VERSION 5.8 ;
BUSBITCHARS "[]" ;
DIVIDERCHAR "/" ;
UNITS
    DATABASE MICRONS 1000 ;
END UNITS

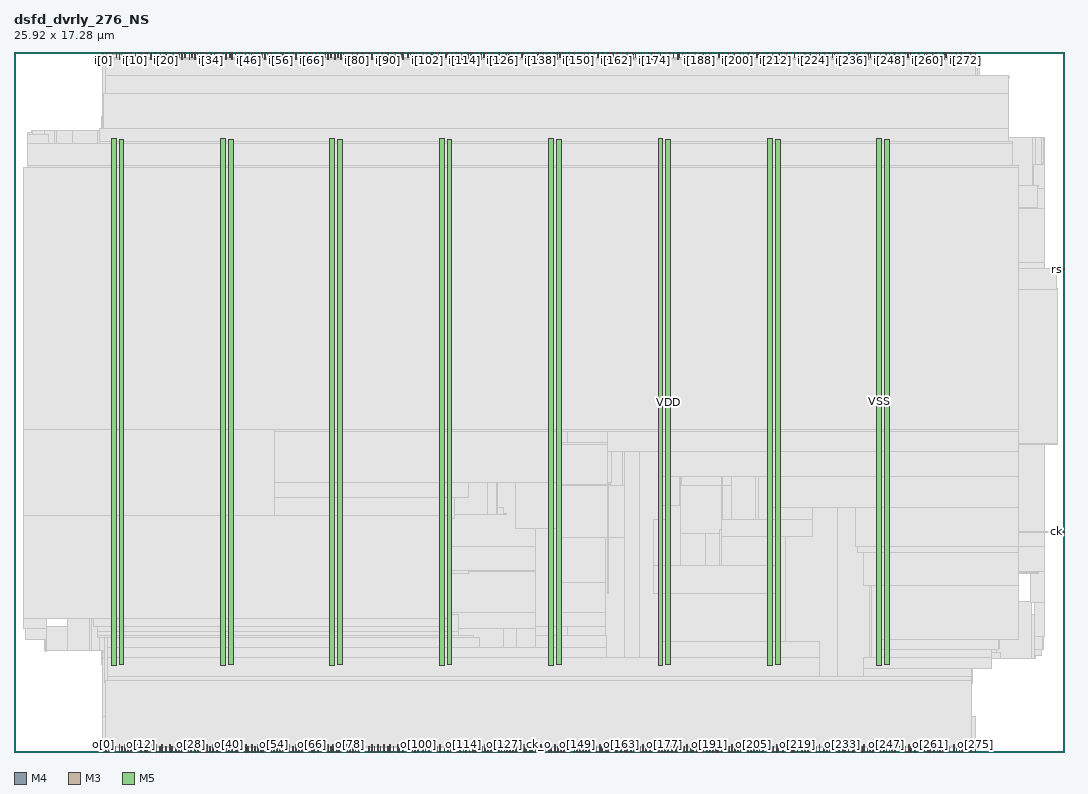
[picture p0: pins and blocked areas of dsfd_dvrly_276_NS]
MACRO dsfd_dvrly_276_NS
  FOREIGN dsfd_dvrly_276_NS 0 0 ;
  CLASS BLOCK ;
  SIZE 25.92 BY 17.28 ;
  PIN ck
    DIRECTION INPUT ;
    USE SIGNAL ;
    PORT
      LAYER M4 ;
        RECT  25.728 5.424 25.92 5.448 ;
    END
  END ck
  PIN ck_o
    DIRECTION OUTPUT ;
    USE SIGNAL ;
    PORT
      LAYER M3 ;
        RECT  12.96 0 12.978 0.144 ;
    END
  END ck_o
  PIN i[0]
    DIRECTION INPUT ;
    USE SIGNAL ;
    PORT
      LAYER M3 ;
        RECT  2.196 17.136 2.214 17.28 ;
    END
  END i[0]
  PIN i[100]
    DIRECTION INPUT ;
    USE SIGNAL ;
    PORT
      LAYER M3 ;
        RECT  10.008 17.136 10.026 17.28 ;
    END
  END i[100]
  PIN i[101]
    DIRECTION INPUT ;
    USE SIGNAL ;
    PORT
      LAYER M5 ;
        RECT  10.08 17.088 10.104 17.28 ;
    END
  END i[101]
  PIN i[102]
    DIRECTION INPUT ;
    USE SIGNAL ;
    PORT
      LAYER M3 ;
        RECT  10.188 17.136 10.206 17.28 ;
    END
  END i[102]
  PIN i[103]
    DIRECTION INPUT ;
    USE SIGNAL ;
    PORT
      LAYER M5 ;
        RECT  10.272 17.088 10.296 17.28 ;
    END
  END i[103]
  PIN i[104]
    DIRECTION INPUT ;
    USE SIGNAL ;
    PORT
      LAYER M3 ;
        RECT  10.332 17.136 10.35 17.28 ;
    END
  END i[104]
  PIN i[105]
    DIRECTION INPUT ;
    USE SIGNAL ;
    PORT
      LAYER M5 ;
        RECT  10.416 17.088 10.44 17.28 ;
    END
  END i[105]
  PIN i[106]
    DIRECTION INPUT ;
    USE SIGNAL ;
    PORT
      LAYER M3 ;
        RECT  10.476 17.136 10.494 17.28 ;
    END
  END i[106]
  PIN i[107]
    DIRECTION INPUT ;
    USE SIGNAL ;
    PORT
      LAYER M5 ;
        RECT  10.56 17.088 10.584 17.28 ;
    END
  END i[107]
  PIN i[108]
    DIRECTION INPUT ;
    USE SIGNAL ;
    PORT
      LAYER M3 ;
        RECT  10.656 17.136 10.674 17.28 ;
    END
  END i[108]
  PIN i[109]
    DIRECTION INPUT ;
    USE SIGNAL ;
    PORT
      LAYER M5 ;
        RECT  10.704 17.088 10.728 17.28 ;
    END
  END i[109]
  PIN i[10]
    DIRECTION INPUT ;
    USE SIGNAL ;
    PORT
      LAYER M3 ;
        RECT  2.988 17.136 3.006 17.28 ;
    END
  END i[10]
  PIN i[110]
    DIRECTION INPUT ;
    USE SIGNAL ;
    PORT
      LAYER M3 ;
        RECT  10.8 17.136 10.818 17.28 ;
    END
  END i[110]
  PIN i[111]
    DIRECTION INPUT ;
    USE SIGNAL ;
    PORT
      LAYER M5 ;
        RECT  10.896 17.088 10.92 17.28 ;
    END
  END i[111]
  PIN i[112]
    DIRECTION INPUT ;
    USE SIGNAL ;
    PORT
      LAYER M3 ;
        RECT  10.944 17.136 10.962 17.28 ;
    END
  END i[112]
  PIN i[113]
    DIRECTION INPUT ;
    USE SIGNAL ;
    PORT
      LAYER M5 ;
        RECT  11.04 17.088 11.064 17.28 ;
    END
  END i[113]
  PIN i[114]
    DIRECTION INPUT ;
    USE SIGNAL ;
    PORT
      LAYER M3 ;
        RECT  11.124 17.136 11.142 17.28 ;
    END
  END i[114]
  PIN i[115]
    DIRECTION INPUT ;
    USE SIGNAL ;
    PORT
      LAYER M5 ;
        RECT  11.184 17.088 11.208 17.28 ;
    END
  END i[115]
  PIN i[116]
    DIRECTION INPUT ;
    USE SIGNAL ;
    PORT
      LAYER M3 ;
        RECT  11.268 17.136 11.286 17.28 ;
    END
  END i[116]
  PIN i[117]
    DIRECTION INPUT ;
    USE SIGNAL ;
    PORT
      LAYER M5 ;
        RECT  11.328 17.088 11.352 17.28 ;
    END
  END i[117]
  PIN i[118]
    DIRECTION INPUT ;
    USE SIGNAL ;
    PORT
      LAYER M3 ;
        RECT  11.412 17.136 11.43 17.28 ;
    END
  END i[118]
  PIN i[119]
    DIRECTION INPUT ;
    USE SIGNAL ;
    PORT
      LAYER M5 ;
        RECT  11.52 17.088 11.544 17.28 ;
    END
  END i[119]
  PIN i[11]
    DIRECTION INPUT ;
    USE SIGNAL ;
    PORT
      LAYER M5 ;
        RECT  3.072 17.088 3.096 17.28 ;
    END
  END i[11]
  PIN i[120]
    DIRECTION INPUT ;
    USE SIGNAL ;
    PORT
      LAYER M3 ;
        RECT  11.592 17.136 11.61 17.28 ;
    END
  END i[120]
  PIN i[121]
    DIRECTION INPUT ;
    USE SIGNAL ;
    PORT
      LAYER M5 ;
        RECT  11.664 17.088 11.688 17.28 ;
    END
  END i[121]
  PIN i[122]
    DIRECTION INPUT ;
    USE SIGNAL ;
    PORT
      LAYER M3 ;
        RECT  11.736 17.136 11.754 17.28 ;
    END
  END i[122]
  PIN i[123]
    DIRECTION INPUT ;
    USE SIGNAL ;
    PORT
      LAYER M5 ;
        RECT  11.808 17.088 11.832 17.28 ;
    END
  END i[123]
  PIN i[124]
    DIRECTION INPUT ;
    USE SIGNAL ;
    PORT
      LAYER M3 ;
        RECT  11.88 17.136 11.898 17.28 ;
    END
  END i[124]
  PIN i[125]
    DIRECTION INPUT ;
    USE SIGNAL ;
    PORT
      LAYER M5 ;
        RECT  11.952 17.088 11.976 17.28 ;
    END
  END i[125]
  PIN i[126]
    DIRECTION INPUT ;
    USE SIGNAL ;
    PORT
      LAYER M3 ;
        RECT  12.06 17.136 12.078 17.28 ;
    END
  END i[126]
  PIN i[127]
    DIRECTION INPUT ;
    USE SIGNAL ;
    PORT
      LAYER M5 ;
        RECT  12.144 17.088 12.168 17.28 ;
    END
  END i[127]
  PIN i[128]
    DIRECTION INPUT ;
    USE SIGNAL ;
    PORT
      LAYER M3 ;
        RECT  12.204 17.136 12.222 17.28 ;
    END
  END i[128]
  PIN i[129]
    DIRECTION INPUT ;
    USE SIGNAL ;
    PORT
      LAYER M5 ;
        RECT  12.288 17.088 12.312 17.28 ;
    END
  END i[129]
  PIN i[12]
    DIRECTION INPUT ;
    USE SIGNAL ;
    PORT
      LAYER M3 ;
        RECT  3.132 17.136 3.15 17.28 ;
    END
  END i[12]
  PIN i[130]
    DIRECTION INPUT ;
    USE SIGNAL ;
    PORT
      LAYER M3 ;
        RECT  12.348 17.136 12.366 17.28 ;
    END
  END i[130]
  PIN i[131]
    DIRECTION INPUT ;
    USE SIGNAL ;
    PORT
      LAYER M5 ;
        RECT  12.432 17.088 12.456 17.28 ;
    END
  END i[131]
  PIN i[132]
    DIRECTION INPUT ;
    USE SIGNAL ;
    PORT
      LAYER M3 ;
        RECT  12.528 17.136 12.546 17.28 ;
    END
  END i[132]
  PIN i[133]
    DIRECTION INPUT ;
    USE SIGNAL ;
    PORT
      LAYER M5 ;
        RECT  12.576 17.088 12.6 17.28 ;
    END
  END i[133]
  PIN i[134]
    DIRECTION INPUT ;
    USE SIGNAL ;
    PORT
      LAYER M3 ;
        RECT  12.672 17.136 12.69 17.28 ;
    END
  END i[134]
  PIN i[135]
    DIRECTION INPUT ;
    USE SIGNAL ;
    PORT
      LAYER M5 ;
        RECT  12.768 17.088 12.792 17.28 ;
    END
  END i[135]
  PIN i[136]
    DIRECTION INPUT ;
    USE SIGNAL ;
    PORT
      LAYER M3 ;
        RECT  12.816 17.136 12.834 17.28 ;
    END
  END i[136]
  PIN i[137]
    DIRECTION INPUT ;
    USE SIGNAL ;
    PORT
      LAYER M5 ;
        RECT  12.912 17.088 12.936 17.28 ;
    END
  END i[137]
  PIN i[138]
    DIRECTION INPUT ;
    USE SIGNAL ;
    PORT
      LAYER M3 ;
        RECT  12.996 17.136 13.014 17.28 ;
    END
  END i[138]
  PIN i[139]
    DIRECTION INPUT ;
    USE SIGNAL ;
    PORT
      LAYER M5 ;
        RECT  13.056 17.088 13.08 17.28 ;
    END
  END i[139]
  PIN i[13]
    DIRECTION INPUT ;
    USE SIGNAL ;
    PORT
      LAYER M5 ;
        RECT  3.216 17.088 3.24 17.28 ;
    END
  END i[13]
  PIN i[140]
    DIRECTION INPUT ;
    USE SIGNAL ;
    PORT
      LAYER M3 ;
        RECT  13.14 17.136 13.158 17.28 ;
    END
  END i[140]
  PIN i[141]
    DIRECTION INPUT ;
    USE SIGNAL ;
    PORT
      LAYER M5 ;
        RECT  13.2 17.088 13.224 17.28 ;
    END
  END i[141]
  PIN i[142]
    DIRECTION INPUT ;
    USE SIGNAL ;
    PORT
      LAYER M3 ;
        RECT  13.32 17.136 13.338 17.28 ;
    END
  END i[142]
  PIN i[143]
    DIRECTION INPUT ;
    USE SIGNAL ;
    PORT
      LAYER M5 ;
        RECT  13.392 17.088 13.416 17.28 ;
    END
  END i[143]
  PIN i[144]
    DIRECTION INPUT ;
    USE SIGNAL ;
    PORT
      LAYER M3 ;
        RECT  13.464 17.136 13.482 17.28 ;
    END
  END i[144]
  PIN i[145]
    DIRECTION INPUT ;
    USE SIGNAL ;
    PORT
      LAYER M5 ;
        RECT  13.536 17.088 13.56 17.28 ;
    END
  END i[145]
  PIN i[146]
    DIRECTION INPUT ;
    USE SIGNAL ;
    PORT
      LAYER M3 ;
        RECT  13.608 17.136 13.626 17.28 ;
    END
  END i[146]
  PIN i[147]
    DIRECTION INPUT ;
    USE SIGNAL ;
    PORT
      LAYER M5 ;
        RECT  13.68 17.088 13.704 17.28 ;
    END
  END i[147]
  PIN i[148]
    DIRECTION INPUT ;
    USE SIGNAL ;
    PORT
      LAYER M3 ;
        RECT  13.788 17.136 13.806 17.28 ;
    END
  END i[148]
  PIN i[149]
    DIRECTION INPUT ;
    USE SIGNAL ;
    PORT
      LAYER M5 ;
        RECT  13.824 17.088 13.848 17.28 ;
    END
  END i[149]
  PIN i[14]
    DIRECTION INPUT ;
    USE SIGNAL ;
    PORT
      LAYER M3 ;
        RECT  3.276 17.136 3.294 17.28 ;
    END
  END i[14]
  PIN i[150]
    DIRECTION INPUT ;
    USE SIGNAL ;
    PORT
      LAYER M3 ;
        RECT  13.932 17.136 13.95 17.28 ;
    END
  END i[150]
  PIN i[151]
    DIRECTION INPUT ;
    USE SIGNAL ;
    PORT
      LAYER M5 ;
        RECT  14.016 17.088 14.04 17.28 ;
    END
  END i[151]
  PIN i[152]
    DIRECTION INPUT ;
    USE SIGNAL ;
    PORT
      LAYER M3 ;
        RECT  14.076 17.136 14.094 17.28 ;
    END
  END i[152]
  PIN i[153]
    DIRECTION INPUT ;
    USE SIGNAL ;
    PORT
      LAYER M5 ;
        RECT  14.16 17.088 14.184 17.28 ;
    END
  END i[153]
  PIN i[154]
    DIRECTION INPUT ;
    USE SIGNAL ;
    PORT
      LAYER M3 ;
        RECT  14.256 17.136 14.274 17.28 ;
    END
  END i[154]
  PIN i[155]
    DIRECTION INPUT ;
    USE SIGNAL ;
    PORT
      LAYER M5 ;
        RECT  14.304 17.088 14.328 17.28 ;
    END
  END i[155]
  PIN i[156]
    DIRECTION INPUT ;
    USE SIGNAL ;
    PORT
      LAYER M3 ;
        RECT  14.4 17.136 14.418 17.28 ;
    END
  END i[156]
  PIN i[157]
    DIRECTION INPUT ;
    USE SIGNAL ;
    PORT
      LAYER M5 ;
        RECT  14.496 17.088 14.52 17.28 ;
    END
  END i[157]
  PIN i[158]
    DIRECTION INPUT ;
    USE SIGNAL ;
    PORT
      LAYER M3 ;
        RECT  14.544 17.136 14.562 17.28 ;
    END
  END i[158]
  PIN i[159]
    DIRECTION INPUT ;
    USE SIGNAL ;
    PORT
      LAYER M5 ;
        RECT  14.64 17.088 14.664 17.28 ;
    END
  END i[159]
  PIN i[15]
    DIRECTION INPUT ;
    USE SIGNAL ;
    PORT
      LAYER M5 ;
        RECT  3.36 17.088 3.384 17.28 ;
    END
  END i[15]
  PIN i[160]
    DIRECTION INPUT ;
    USE SIGNAL ;
    PORT
      LAYER M3 ;
        RECT  14.724 17.136 14.742 17.28 ;
    END
  END i[160]
  PIN i[161]
    DIRECTION INPUT ;
    USE SIGNAL ;
    PORT
      LAYER M5 ;
        RECT  14.784 17.088 14.808 17.28 ;
    END
  END i[161]
  PIN i[162]
    DIRECTION INPUT ;
    USE SIGNAL ;
    PORT
      LAYER M3 ;
        RECT  14.868 17.136 14.886 17.28 ;
    END
  END i[162]
  PIN i[163]
    DIRECTION INPUT ;
    USE SIGNAL ;
    PORT
      LAYER M5 ;
        RECT  14.928 17.088 14.952 17.28 ;
    END
  END i[163]
  PIN i[164]
    DIRECTION INPUT ;
    USE SIGNAL ;
    PORT
      LAYER M3 ;
        RECT  15.012 17.136 15.03 17.28 ;
    END
  END i[164]
  PIN i[165]
    DIRECTION INPUT ;
    USE SIGNAL ;
    PORT
      LAYER M5 ;
        RECT  15.12 17.088 15.144 17.28 ;
    END
  END i[165]
  PIN i[166]
    DIRECTION INPUT ;
    USE SIGNAL ;
    PORT
      LAYER M3 ;
        RECT  15.192 17.136 15.21 17.28 ;
    END
  END i[166]
  PIN i[167]
    DIRECTION INPUT ;
    USE SIGNAL ;
    PORT
      LAYER M5 ;
        RECT  15.264 17.088 15.288 17.28 ;
    END
  END i[167]
  PIN i[168]
    DIRECTION INPUT ;
    USE SIGNAL ;
    PORT
      LAYER M3 ;
        RECT  15.336 17.136 15.354 17.28 ;
    END
  END i[168]
  PIN i[169]
    DIRECTION INPUT ;
    USE SIGNAL ;
    PORT
      LAYER M5 ;
        RECT  15.408 17.088 15.432 17.28 ;
    END
  END i[169]
  PIN i[16]
    DIRECTION INPUT ;
    USE SIGNAL ;
    PORT
      LAYER M3 ;
        RECT  3.456 17.136 3.474 17.28 ;
    END
  END i[16]
  PIN i[170]
    DIRECTION INPUT ;
    USE SIGNAL ;
    PORT
      LAYER M3 ;
        RECT  15.48 17.136 15.498 17.28 ;
    END
  END i[170]
  PIN i[171]
    DIRECTION INPUT ;
    USE SIGNAL ;
    PORT
      LAYER M5 ;
        RECT  15.552 17.088 15.576 17.28 ;
    END
  END i[171]
  PIN i[172]
    DIRECTION INPUT ;
    USE SIGNAL ;
    PORT
      LAYER M3 ;
        RECT  15.66 17.136 15.678 17.28 ;
    END
  END i[172]
  PIN i[173]
    DIRECTION INPUT ;
    USE SIGNAL ;
    PORT
      LAYER M5 ;
        RECT  15.744 17.088 15.768 17.28 ;
    END
  END i[173]
  PIN i[174]
    DIRECTION INPUT ;
    USE SIGNAL ;
    PORT
      LAYER M3 ;
        RECT  15.804 17.136 15.822 17.28 ;
    END
  END i[174]
  PIN i[175]
    DIRECTION INPUT ;
    USE SIGNAL ;
    PORT
      LAYER M5 ;
        RECT  15.888 17.088 15.912 17.28 ;
    END
  END i[175]
  PIN i[176]
    DIRECTION INPUT ;
    USE SIGNAL ;
    PORT
      LAYER M3 ;
        RECT  15.948 17.136 15.966 17.28 ;
    END
  END i[176]
  PIN i[177]
    DIRECTION INPUT ;
    USE SIGNAL ;
    PORT
      LAYER M5 ;
        RECT  16.032 17.088 16.056 17.28 ;
    END
  END i[177]
  PIN i[178]
    DIRECTION INPUT ;
    USE SIGNAL ;
    PORT
      LAYER M3 ;
        RECT  16.128 17.136 16.146 17.28 ;
    END
  END i[178]
  PIN i[179]
    DIRECTION INPUT ;
    USE SIGNAL ;
    PORT
      LAYER M5 ;
        RECT  16.176 17.088 16.2 17.28 ;
    END
  END i[179]
  PIN i[17]
    DIRECTION INPUT ;
    USE SIGNAL ;
    PORT
      LAYER M5 ;
        RECT  3.504 17.088 3.528 17.28 ;
    END
  END i[17]
  PIN i[180]
    DIRECTION INPUT ;
    USE SIGNAL ;
    PORT
      LAYER M3 ;
        RECT  16.272 17.136 16.29 17.28 ;
    END
  END i[180]
  PIN i[181]
    DIRECTION INPUT ;
    USE SIGNAL ;
    PORT
      LAYER M5 ;
        RECT  16.368 17.088 16.392 17.28 ;
    END
  END i[181]
  PIN i[182]
    DIRECTION INPUT ;
    USE SIGNAL ;
    PORT
      LAYER M3 ;
        RECT  16.416 17.136 16.434 17.28 ;
    END
  END i[182]
  PIN i[183]
    DIRECTION INPUT ;
    USE SIGNAL ;
    PORT
      LAYER M5 ;
        RECT  16.512 17.088 16.536 17.28 ;
    END
  END i[183]
  PIN i[184]
    DIRECTION INPUT ;
    USE SIGNAL ;
    PORT
      LAYER M3 ;
        RECT  16.596 17.136 16.614 17.28 ;
    END
  END i[184]
  PIN i[185]
    DIRECTION INPUT ;
    USE SIGNAL ;
    PORT
      LAYER M5 ;
        RECT  16.656 17.088 16.68 17.28 ;
    END
  END i[185]
  PIN i[186]
    DIRECTION INPUT ;
    USE SIGNAL ;
    PORT
      LAYER M3 ;
        RECT  16.74 17.136 16.758 17.28 ;
    END
  END i[186]
  PIN i[187]
    DIRECTION INPUT ;
    USE SIGNAL ;
    PORT
      LAYER M5 ;
        RECT  16.8 17.088 16.824 17.28 ;
    END
  END i[187]
  PIN i[188]
    DIRECTION INPUT ;
    USE SIGNAL ;
    PORT
      LAYER M3 ;
        RECT  16.92 17.136 16.938 17.28 ;
    END
  END i[188]
  PIN i[189]
    DIRECTION INPUT ;
    USE SIGNAL ;
    PORT
      LAYER M5 ;
        RECT  16.992 17.088 17.016 17.28 ;
    END
  END i[189]
  PIN i[18]
    DIRECTION INPUT ;
    USE SIGNAL ;
    PORT
      LAYER M3 ;
        RECT  3.6 17.136 3.618 17.28 ;
    END
  END i[18]
  PIN i[190]
    DIRECTION INPUT ;
    USE SIGNAL ;
    PORT
      LAYER M3 ;
        RECT  17.064 17.136 17.082 17.28 ;
    END
  END i[190]
  PIN i[191]
    DIRECTION INPUT ;
    USE SIGNAL ;
    PORT
      LAYER M5 ;
        RECT  17.136 17.088 17.16 17.28 ;
    END
  END i[191]
  PIN i[192]
    DIRECTION INPUT ;
    USE SIGNAL ;
    PORT
      LAYER M3 ;
        RECT  17.208 17.136 17.226 17.28 ;
    END
  END i[192]
  PIN i[193]
    DIRECTION INPUT ;
    USE SIGNAL ;
    PORT
      LAYER M5 ;
        RECT  17.28 17.088 17.304 17.28 ;
    END
  END i[193]
  PIN i[194]
    DIRECTION INPUT ;
    USE SIGNAL ;
    PORT
      LAYER M3 ;
        RECT  17.388 17.136 17.406 17.28 ;
    END
  END i[194]
  PIN i[195]
    DIRECTION INPUT ;
    USE SIGNAL ;
    PORT
      LAYER M5 ;
        RECT  17.472 17.088 17.496 17.28 ;
    END
  END i[195]
  PIN i[196]
    DIRECTION INPUT ;
    USE SIGNAL ;
    PORT
      LAYER M3 ;
        RECT  17.532 17.136 17.55 17.28 ;
    END
  END i[196]
  PIN i[197]
    DIRECTION INPUT ;
    USE SIGNAL ;
    PORT
      LAYER M5 ;
        RECT  17.616 17.088 17.64 17.28 ;
    END
  END i[197]
  PIN i[198]
    DIRECTION INPUT ;
    USE SIGNAL ;
    PORT
      LAYER M3 ;
        RECT  17.676 17.136 17.694 17.28 ;
    END
  END i[198]
  PIN i[199]
    DIRECTION INPUT ;
    USE SIGNAL ;
    PORT
      LAYER M5 ;
        RECT  17.76 17.088 17.784 17.28 ;
    END
  END i[199]
  PIN i[19]
    DIRECTION INPUT ;
    USE SIGNAL ;
    PORT
      LAYER M5 ;
        RECT  3.696 17.088 3.72 17.28 ;
    END
  END i[19]
  PIN i[1]
    DIRECTION INPUT ;
    USE SIGNAL ;
    PORT
      LAYER M5 ;
        RECT  2.256 17.088 2.28 17.28 ;
    END
  END i[1]
  PIN i[200]
    DIRECTION INPUT ;
    USE SIGNAL ;
    PORT
      LAYER M3 ;
        RECT  17.856 17.136 17.874 17.28 ;
    END
  END i[200]
  PIN i[201]
    DIRECTION INPUT ;
    USE SIGNAL ;
    PORT
      LAYER M5 ;
        RECT  17.904 17.088 17.928 17.28 ;
    END
  END i[201]
  PIN i[202]
    DIRECTION INPUT ;
    USE SIGNAL ;
    PORT
      LAYER M3 ;
        RECT  18 17.136 18.018 17.28 ;
    END
  END i[202]
  PIN i[203]
    DIRECTION INPUT ;
    USE SIGNAL ;
    PORT
      LAYER M5 ;
        RECT  18.096 17.088 18.12 17.28 ;
    END
  END i[203]
  PIN i[204]
    DIRECTION INPUT ;
    USE SIGNAL ;
    PORT
      LAYER M3 ;
        RECT  18.144 17.136 18.162 17.28 ;
    END
  END i[204]
  PIN i[205]
    DIRECTION INPUT ;
    USE SIGNAL ;
    PORT
      LAYER M5 ;
        RECT  18.24 17.088 18.264 17.28 ;
    END
  END i[205]
  PIN i[206]
    DIRECTION INPUT ;
    USE SIGNAL ;
    PORT
      LAYER M3 ;
        RECT  18.324 17.136 18.342 17.28 ;
    END
  END i[206]
  PIN i[207]
    DIRECTION INPUT ;
    USE SIGNAL ;
    PORT
      LAYER M5 ;
        RECT  18.384 17.088 18.408 17.28 ;
    END
  END i[207]
  PIN i[208]
    DIRECTION INPUT ;
    USE SIGNAL ;
    PORT
      LAYER M3 ;
        RECT  18.468 17.136 18.486 17.28 ;
    END
  END i[208]
  PIN i[209]
    DIRECTION INPUT ;
    USE SIGNAL ;
    PORT
      LAYER M5 ;
        RECT  18.528 17.088 18.552 17.28 ;
    END
  END i[209]
  PIN i[20]
    DIRECTION INPUT ;
    USE SIGNAL ;
    PORT
      LAYER M3 ;
        RECT  3.744 17.136 3.762 17.28 ;
    END
  END i[20]
  PIN i[210]
    DIRECTION INPUT ;
    USE SIGNAL ;
    PORT
      LAYER M3 ;
        RECT  18.612 17.136 18.63 17.28 ;
    END
  END i[210]
  PIN i[211]
    DIRECTION INPUT ;
    USE SIGNAL ;
    PORT
      LAYER M5 ;
        RECT  18.72 17.088 18.744 17.28 ;
    END
  END i[211]
  PIN i[212]
    DIRECTION INPUT ;
    USE SIGNAL ;
    PORT
      LAYER M3 ;
        RECT  18.792 17.136 18.81 17.28 ;
    END
  END i[212]
  PIN i[213]
    DIRECTION INPUT ;
    USE SIGNAL ;
    PORT
      LAYER M5 ;
        RECT  18.864 17.088 18.888 17.28 ;
    END
  END i[213]
  PIN i[214]
    DIRECTION INPUT ;
    USE SIGNAL ;
    PORT
      LAYER M3 ;
        RECT  18.936 17.136 18.954 17.28 ;
    END
  END i[214]
  PIN i[215]
    DIRECTION INPUT ;
    USE SIGNAL ;
    PORT
      LAYER M5 ;
        RECT  19.008 17.088 19.032 17.28 ;
    END
  END i[215]
  PIN i[216]
    DIRECTION INPUT ;
    USE SIGNAL ;
    PORT
      LAYER M3 ;
        RECT  19.08 17.136 19.098 17.28 ;
    END
  END i[216]
  PIN i[217]
    DIRECTION INPUT ;
    USE SIGNAL ;
    PORT
      LAYER M5 ;
        RECT  19.152 17.088 19.176 17.28 ;
    END
  END i[217]
  PIN i[218]
    DIRECTION INPUT ;
    USE SIGNAL ;
    PORT
      LAYER M3 ;
        RECT  19.26 17.136 19.278 17.28 ;
    END
  END i[218]
  PIN i[219]
    DIRECTION INPUT ;
    USE SIGNAL ;
    PORT
      LAYER M5 ;
        RECT  19.344 17.088 19.368 17.28 ;
    END
  END i[219]
  PIN i[21]
    DIRECTION INPUT ;
    USE SIGNAL ;
    PORT
      LAYER M5 ;
        RECT  3.84 17.088 3.864 17.28 ;
    END
  END i[21]
  PIN i[220]
    DIRECTION INPUT ;
    USE SIGNAL ;
    PORT
      LAYER M3 ;
        RECT  19.404 17.136 19.422 17.28 ;
    END
  END i[220]
  PIN i[221]
    DIRECTION INPUT ;
    USE SIGNAL ;
    PORT
      LAYER M5 ;
        RECT  19.488 17.088 19.512 17.28 ;
    END
  END i[221]
  PIN i[222]
    DIRECTION INPUT ;
    USE SIGNAL ;
    PORT
      LAYER M3 ;
        RECT  19.548 17.136 19.566 17.28 ;
    END
  END i[222]
  PIN i[223]
    DIRECTION INPUT ;
    USE SIGNAL ;
    PORT
      LAYER M5 ;
        RECT  19.632 17.088 19.656 17.28 ;
    END
  END i[223]
  PIN i[224]
    DIRECTION INPUT ;
    USE SIGNAL ;
    PORT
      LAYER M3 ;
        RECT  19.728 17.136 19.746 17.28 ;
    END
  END i[224]
  PIN i[225]
    DIRECTION INPUT ;
    USE SIGNAL ;
    PORT
      LAYER M5 ;
        RECT  19.776 17.088 19.8 17.28 ;
    END
  END i[225]
  PIN i[226]
    DIRECTION INPUT ;
    USE SIGNAL ;
    PORT
      LAYER M3 ;
        RECT  19.872 17.136 19.89 17.28 ;
    END
  END i[226]
  PIN i[227]
    DIRECTION INPUT ;
    USE SIGNAL ;
    PORT
      LAYER M5 ;
        RECT  19.968 17.088 19.992 17.28 ;
    END
  END i[227]
  PIN i[228]
    DIRECTION INPUT ;
    USE SIGNAL ;
    PORT
      LAYER M3 ;
        RECT  20.016 17.136 20.034 17.28 ;
    END
  END i[228]
  PIN i[229]
    DIRECTION INPUT ;
    USE SIGNAL ;
    PORT
      LAYER M5 ;
        RECT  20.112 17.088 20.136 17.28 ;
    END
  END i[229]
  PIN i[22]
    DIRECTION INPUT ;
    USE SIGNAL ;
    PORT
      LAYER M3 ;
        RECT  3.924 17.136 3.942 17.28 ;
    END
  END i[22]
  PIN i[230]
    DIRECTION INPUT ;
    USE SIGNAL ;
    PORT
      LAYER M3 ;
        RECT  20.196 17.136 20.214 17.28 ;
    END
  END i[230]
  PIN i[231]
    DIRECTION INPUT ;
    USE SIGNAL ;
    PORT
      LAYER M5 ;
        RECT  20.256 17.088 20.28 17.28 ;
    END
  END i[231]
  PIN i[232]
    DIRECTION INPUT ;
    USE SIGNAL ;
    PORT
      LAYER M3 ;
        RECT  20.34 17.136 20.358 17.28 ;
    END
  END i[232]
  PIN i[233]
    DIRECTION INPUT ;
    USE SIGNAL ;
    PORT
      LAYER M5 ;
        RECT  20.4 17.088 20.424 17.28 ;
    END
  END i[233]
  PIN i[234]
    DIRECTION INPUT ;
    USE SIGNAL ;
    PORT
      LAYER M3 ;
        RECT  20.52 17.136 20.538 17.28 ;
    END
  END i[234]
  PIN i[235]
    DIRECTION INPUT ;
    USE SIGNAL ;
    PORT
      LAYER M5 ;
        RECT  20.592 17.088 20.616 17.28 ;
    END
  END i[235]
  PIN i[236]
    DIRECTION INPUT ;
    USE SIGNAL ;
    PORT
      LAYER M3 ;
        RECT  20.664 17.136 20.682 17.28 ;
    END
  END i[236]
  PIN i[237]
    DIRECTION INPUT ;
    USE SIGNAL ;
    PORT
      LAYER M5 ;
        RECT  20.736 17.088 20.76 17.28 ;
    END
  END i[237]
  PIN i[238]
    DIRECTION INPUT ;
    USE SIGNAL ;
    PORT
      LAYER M3 ;
        RECT  20.808 17.136 20.826 17.28 ;
    END
  END i[238]
  PIN i[239]
    DIRECTION INPUT ;
    USE SIGNAL ;
    PORT
      LAYER M5 ;
        RECT  20.88 17.088 20.904 17.28 ;
    END
  END i[239]
  PIN i[23]
    DIRECTION INPUT ;
    USE SIGNAL ;
    PORT
      LAYER M5 ;
        RECT  3.984 17.088 4.008 17.28 ;
    END
  END i[23]
  PIN i[240]
    DIRECTION INPUT ;
    USE SIGNAL ;
    PORT
      LAYER M3 ;
        RECT  20.988 17.136 21.006 17.28 ;
    END
  END i[240]
  PIN i[241]
    DIRECTION INPUT ;
    USE SIGNAL ;
    PORT
      LAYER M5 ;
        RECT  21.072 17.088 21.096 17.28 ;
    END
  END i[241]
  PIN i[242]
    DIRECTION INPUT ;
    USE SIGNAL ;
    PORT
      LAYER M3 ;
        RECT  21.132 17.136 21.15 17.28 ;
    END
  END i[242]
  PIN i[243]
    DIRECTION INPUT ;
    USE SIGNAL ;
    PORT
      LAYER M5 ;
        RECT  21.216 17.088 21.24 17.28 ;
    END
  END i[243]
  PIN i[244]
    DIRECTION INPUT ;
    USE SIGNAL ;
    PORT
      LAYER M3 ;
        RECT  21.276 17.136 21.294 17.28 ;
    END
  END i[244]
  PIN i[245]
    DIRECTION INPUT ;
    USE SIGNAL ;
    PORT
      LAYER M5 ;
        RECT  21.36 17.088 21.384 17.28 ;
    END
  END i[245]
  PIN i[246]
    DIRECTION INPUT ;
    USE SIGNAL ;
    PORT
      LAYER M3 ;
        RECT  21.456 17.136 21.474 17.28 ;
    END
  END i[246]
  PIN i[247]
    DIRECTION INPUT ;
    USE SIGNAL ;
    PORT
      LAYER M5 ;
        RECT  21.504 17.088 21.528 17.28 ;
    END
  END i[247]
  PIN i[248]
    DIRECTION INPUT ;
    USE SIGNAL ;
    PORT
      LAYER M3 ;
        RECT  21.6 17.136 21.618 17.28 ;
    END
  END i[248]
  PIN i[249]
    DIRECTION INPUT ;
    USE SIGNAL ;
    PORT
      LAYER M5 ;
        RECT  21.696 17.088 21.72 17.28 ;
    END
  END i[249]
  PIN i[24]
    DIRECTION INPUT ;
    USE SIGNAL ;
    PORT
      LAYER M3 ;
        RECT  4.068 17.136 4.086 17.28 ;
    END
  END i[24]
  PIN i[250]
    DIRECTION INPUT ;
    USE SIGNAL ;
    PORT
      LAYER M3 ;
        RECT  21.744 17.136 21.762 17.28 ;
    END
  END i[250]
  PIN i[251]
    DIRECTION INPUT ;
    USE SIGNAL ;
    PORT
      LAYER M5 ;
        RECT  21.84 17.088 21.864 17.28 ;
    END
  END i[251]
  PIN i[252]
    DIRECTION INPUT ;
    USE SIGNAL ;
    PORT
      LAYER M3 ;
        RECT  21.924 17.136 21.942 17.28 ;
    END
  END i[252]
  PIN i[253]
    DIRECTION INPUT ;
    USE SIGNAL ;
    PORT
      LAYER M5 ;
        RECT  21.984 17.088 22.008 17.28 ;
    END
  END i[253]
  PIN i[254]
    DIRECTION INPUT ;
    USE SIGNAL ;
    PORT
      LAYER M3 ;
        RECT  22.068 17.136 22.086 17.28 ;
    END
  END i[254]
  PIN i[255]
    DIRECTION INPUT ;
    USE SIGNAL ;
    PORT
      LAYER M5 ;
        RECT  22.128 17.088 22.152 17.28 ;
    END
  END i[255]
  PIN i[256]
    DIRECTION INPUT ;
    USE SIGNAL ;
    PORT
      LAYER M3 ;
        RECT  22.212 17.136 22.23 17.28 ;
    END
  END i[256]
  PIN i[257]
    DIRECTION INPUT ;
    USE SIGNAL ;
    PORT
      LAYER M5 ;
        RECT  22.32 17.088 22.344 17.28 ;
    END
  END i[257]
  PIN i[258]
    DIRECTION INPUT ;
    USE SIGNAL ;
    PORT
      LAYER M3 ;
        RECT  22.392 17.136 22.41 17.28 ;
    END
  END i[258]
  PIN i[259]
    DIRECTION INPUT ;
    USE SIGNAL ;
    PORT
      LAYER M5 ;
        RECT  22.464 17.088 22.488 17.28 ;
    END
  END i[259]
  PIN i[25]
    DIRECTION INPUT ;
    USE SIGNAL ;
    PORT
      LAYER M5 ;
        RECT  4.128 17.088 4.152 17.28 ;
    END
  END i[25]
  PIN i[260]
    DIRECTION INPUT ;
    USE SIGNAL ;
    PORT
      LAYER M3 ;
        RECT  22.536 17.136 22.554 17.28 ;
    END
  END i[260]
  PIN i[261]
    DIRECTION INPUT ;
    USE SIGNAL ;
    PORT
      LAYER M5 ;
        RECT  22.608 17.088 22.632 17.28 ;
    END
  END i[261]
  PIN i[262]
    DIRECTION INPUT ;
    USE SIGNAL ;
    PORT
      LAYER M3 ;
        RECT  22.68 17.136 22.698 17.28 ;
    END
  END i[262]
  PIN i[263]
    DIRECTION INPUT ;
    USE SIGNAL ;
    PORT
      LAYER M5 ;
        RECT  22.752 17.088 22.776 17.28 ;
    END
  END i[263]
  PIN i[264]
    DIRECTION INPUT ;
    USE SIGNAL ;
    PORT
      LAYER M3 ;
        RECT  22.86 17.136 22.878 17.28 ;
    END
  END i[264]
  PIN i[265]
    DIRECTION INPUT ;
    USE SIGNAL ;
    PORT
      LAYER M5 ;
        RECT  22.944 17.088 22.968 17.28 ;
    END
  END i[265]
  PIN i[266]
    DIRECTION INPUT ;
    USE SIGNAL ;
    PORT
      LAYER M3 ;
        RECT  23.004 17.136 23.022 17.28 ;
    END
  END i[266]
  PIN i[267]
    DIRECTION INPUT ;
    USE SIGNAL ;
    PORT
      LAYER M5 ;
        RECT  23.088 17.088 23.112 17.28 ;
    END
  END i[267]
  PIN i[268]
    DIRECTION INPUT ;
    USE SIGNAL ;
    PORT
      LAYER M3 ;
        RECT  23.148 17.136 23.166 17.28 ;
    END
  END i[268]
  PIN i[269]
    DIRECTION INPUT ;
    USE SIGNAL ;
    PORT
      LAYER M5 ;
        RECT  23.232 17.088 23.256 17.28 ;
    END
  END i[269]
  PIN i[26]
    DIRECTION INPUT ;
    USE SIGNAL ;
    PORT
      LAYER M3 ;
        RECT  4.212 17.136 4.23 17.28 ;
    END
  END i[26]
  PIN i[270]
    DIRECTION INPUT ;
    USE SIGNAL ;
    PORT
      LAYER M3 ;
        RECT  23.328 17.136 23.346 17.28 ;
    END
  END i[270]
  PIN i[271]
    DIRECTION INPUT ;
    USE SIGNAL ;
    PORT
      LAYER M5 ;
        RECT  23.376 17.088 23.4 17.28 ;
    END
  END i[271]
  PIN i[272]
    DIRECTION INPUT ;
    USE SIGNAL ;
    PORT
      LAYER M3 ;
        RECT  23.472 17.136 23.49 17.28 ;
    END
  END i[272]
  PIN i[273]
    DIRECTION INPUT ;
    USE SIGNAL ;
    PORT
      LAYER M5 ;
        RECT  23.568 17.088 23.592 17.28 ;
    END
  END i[273]
  PIN i[274]
    DIRECTION INPUT ;
    USE SIGNAL ;
    PORT
      LAYER M3 ;
        RECT  23.616 17.136 23.634 17.28 ;
    END
  END i[274]
  PIN i[275]
    DIRECTION INPUT ;
    USE SIGNAL ;
    PORT
      LAYER M5 ;
        RECT  23.712 17.088 23.736 17.28 ;
    END
  END i[275]
  PIN i[27]
    DIRECTION INPUT ;
    USE SIGNAL ;
    PORT
      LAYER M5 ;
        RECT  4.32 17.088 4.344 17.28 ;
    END
  END i[27]
  PIN i[28]
    DIRECTION INPUT ;
    USE SIGNAL ;
    PORT
      LAYER M3 ;
        RECT  4.392 17.136 4.41 17.28 ;
    END
  END i[28]
  PIN i[29]
    DIRECTION INPUT ;
    USE SIGNAL ;
    PORT
      LAYER M5 ;
        RECT  4.464 17.088 4.488 17.28 ;
    END
  END i[29]
  PIN i[2]
    DIRECTION INPUT ;
    USE SIGNAL ;
    PORT
      LAYER M3 ;
        RECT  2.34 17.136 2.358 17.28 ;
    END
  END i[2]
  PIN i[30]
    DIRECTION INPUT ;
    USE SIGNAL ;
    PORT
      LAYER M3 ;
        RECT  4.536 17.136 4.554 17.28 ;
    END
  END i[30]
  PIN i[31]
    DIRECTION INPUT ;
    USE SIGNAL ;
    PORT
      LAYER M5 ;
        RECT  4.608 17.088 4.632 17.28 ;
    END
  END i[31]
  PIN i[32]
    DIRECTION INPUT ;
    USE SIGNAL ;
    PORT
      LAYER M3 ;
        RECT  4.68 17.136 4.698 17.28 ;
    END
  END i[32]
  PIN i[33]
    DIRECTION INPUT ;
    USE SIGNAL ;
    PORT
      LAYER M5 ;
        RECT  4.752 17.088 4.776 17.28 ;
    END
  END i[33]
  PIN i[34]
    DIRECTION INPUT ;
    USE SIGNAL ;
    PORT
      LAYER M3 ;
        RECT  4.86 17.136 4.878 17.28 ;
    END
  END i[34]
  PIN i[35]
    DIRECTION INPUT ;
    USE SIGNAL ;
    PORT
      LAYER M5 ;
        RECT  4.944 17.088 4.968 17.28 ;
    END
  END i[35]
  PIN i[36]
    DIRECTION INPUT ;
    USE SIGNAL ;
    PORT
      LAYER M3 ;
        RECT  5.004 17.136 5.022 17.28 ;
    END
  END i[36]
  PIN i[37]
    DIRECTION INPUT ;
    USE SIGNAL ;
    PORT
      LAYER M5 ;
        RECT  5.088 17.088 5.112 17.28 ;
    END
  END i[37]
  PIN i[38]
    DIRECTION INPUT ;
    USE SIGNAL ;
    PORT
      LAYER M3 ;
        RECT  5.148 17.136 5.166 17.28 ;
    END
  END i[38]
  PIN i[39]
    DIRECTION INPUT ;
    USE SIGNAL ;
    PORT
      LAYER M5 ;
        RECT  5.232 17.088 5.256 17.28 ;
    END
  END i[39]
  PIN i[3]
    DIRECTION INPUT ;
    USE SIGNAL ;
    PORT
      LAYER M5 ;
        RECT  2.4 17.088 2.424 17.28 ;
    END
  END i[3]
  PIN i[40]
    DIRECTION INPUT ;
    USE SIGNAL ;
    PORT
      LAYER M3 ;
        RECT  5.328 17.136 5.346 17.28 ;
    END
  END i[40]
  PIN i[41]
    DIRECTION INPUT ;
    USE SIGNAL ;
    PORT
      LAYER M5 ;
        RECT  5.376 17.088 5.4 17.28 ;
    END
  END i[41]
  PIN i[42]
    DIRECTION INPUT ;
    USE SIGNAL ;
    PORT
      LAYER M3 ;
        RECT  5.472 17.136 5.49 17.28 ;
    END
  END i[42]
  PIN i[43]
    DIRECTION INPUT ;
    USE SIGNAL ;
    PORT
      LAYER M5 ;
        RECT  5.568 17.088 5.592 17.28 ;
    END
  END i[43]
  PIN i[44]
    DIRECTION INPUT ;
    USE SIGNAL ;
    PORT
      LAYER M3 ;
        RECT  5.616 17.136 5.634 17.28 ;
    END
  END i[44]
  PIN i[45]
    DIRECTION INPUT ;
    USE SIGNAL ;
    PORT
      LAYER M5 ;
        RECT  5.712 17.088 5.736 17.28 ;
    END
  END i[45]
  PIN i[46]
    DIRECTION INPUT ;
    USE SIGNAL ;
    PORT
      LAYER M3 ;
        RECT  5.796 17.136 5.814 17.28 ;
    END
  END i[46]
  PIN i[47]
    DIRECTION INPUT ;
    USE SIGNAL ;
    PORT
      LAYER M5 ;
        RECT  5.856 17.088 5.88 17.28 ;
    END
  END i[47]
  PIN i[48]
    DIRECTION INPUT ;
    USE SIGNAL ;
    PORT
      LAYER M3 ;
        RECT  5.94 17.136 5.958 17.28 ;
    END
  END i[48]
  PIN i[49]
    DIRECTION INPUT ;
    USE SIGNAL ;
    PORT
      LAYER M5 ;
        RECT  6 17.088 6.024 17.28 ;
    END
  END i[49]
  PIN i[4]
    DIRECTION INPUT ;
    USE SIGNAL ;
    PORT
      LAYER M3 ;
        RECT  2.52 17.136 2.538 17.28 ;
    END
  END i[4]
  PIN i[50]
    DIRECTION INPUT ;
    USE SIGNAL ;
    PORT
      LAYER M3 ;
        RECT  6.12 17.136 6.138 17.28 ;
    END
  END i[50]
  PIN i[51]
    DIRECTION INPUT ;
    USE SIGNAL ;
    PORT
      LAYER M5 ;
        RECT  6.192 17.088 6.216 17.28 ;
    END
  END i[51]
  PIN i[52]
    DIRECTION INPUT ;
    USE SIGNAL ;
    PORT
      LAYER M3 ;
        RECT  6.264 17.136 6.282 17.28 ;
    END
  END i[52]
  PIN i[53]
    DIRECTION INPUT ;
    USE SIGNAL ;
    PORT
      LAYER M5 ;
        RECT  6.336 17.088 6.36 17.28 ;
    END
  END i[53]
  PIN i[54]
    DIRECTION INPUT ;
    USE SIGNAL ;
    PORT
      LAYER M3 ;
        RECT  6.408 17.136 6.426 17.28 ;
    END
  END i[54]
  PIN i[55]
    DIRECTION INPUT ;
    USE SIGNAL ;
    PORT
      LAYER M5 ;
        RECT  6.48 17.088 6.504 17.28 ;
    END
  END i[55]
  PIN i[56]
    DIRECTION INPUT ;
    USE SIGNAL ;
    PORT
      LAYER M3 ;
        RECT  6.588 17.136 6.606 17.28 ;
    END
  END i[56]
  PIN i[57]
    DIRECTION INPUT ;
    USE SIGNAL ;
    PORT
      LAYER M5 ;
        RECT  6.624 17.088 6.648 17.28 ;
    END
  END i[57]
  PIN i[58]
    DIRECTION INPUT ;
    USE SIGNAL ;
    PORT
      LAYER M3 ;
        RECT  6.732 17.136 6.75 17.28 ;
    END
  END i[58]
  PIN i[59]
    DIRECTION INPUT ;
    USE SIGNAL ;
    PORT
      LAYER M5 ;
        RECT  6.816 17.088 6.84 17.28 ;
    END
  END i[59]
  PIN i[5]
    DIRECTION INPUT ;
    USE SIGNAL ;
    PORT
      LAYER M5 ;
        RECT  2.592 17.088 2.616 17.28 ;
    END
  END i[5]
  PIN i[60]
    DIRECTION INPUT ;
    USE SIGNAL ;
    PORT
      LAYER M3 ;
        RECT  6.876 17.136 6.894 17.28 ;
    END
  END i[60]
  PIN i[61]
    DIRECTION INPUT ;
    USE SIGNAL ;
    PORT
      LAYER M5 ;
        RECT  6.96 17.088 6.984 17.28 ;
    END
  END i[61]
  PIN i[62]
    DIRECTION INPUT ;
    USE SIGNAL ;
    PORT
      LAYER M3 ;
        RECT  7.056 17.136 7.074 17.28 ;
    END
  END i[62]
  PIN i[63]
    DIRECTION INPUT ;
    USE SIGNAL ;
    PORT
      LAYER M5 ;
        RECT  7.104 17.088 7.128 17.28 ;
    END
  END i[63]
  PIN i[64]
    DIRECTION INPUT ;
    USE SIGNAL ;
    PORT
      LAYER M3 ;
        RECT  7.2 17.136 7.218 17.28 ;
    END
  END i[64]
  PIN i[65]
    DIRECTION INPUT ;
    USE SIGNAL ;
    PORT
      LAYER M5 ;
        RECT  7.296 17.088 7.32 17.28 ;
    END
  END i[65]
  PIN i[66]
    DIRECTION INPUT ;
    USE SIGNAL ;
    PORT
      LAYER M3 ;
        RECT  7.344 17.136 7.362 17.28 ;
    END
  END i[66]
  PIN i[67]
    DIRECTION INPUT ;
    USE SIGNAL ;
    PORT
      LAYER M5 ;
        RECT  7.44 17.088 7.464 17.28 ;
    END
  END i[67]
  PIN i[68]
    DIRECTION INPUT ;
    USE SIGNAL ;
    PORT
      LAYER M3 ;
        RECT  7.524 17.136 7.542 17.28 ;
    END
  END i[68]
  PIN i[69]
    DIRECTION INPUT ;
    USE SIGNAL ;
    PORT
      LAYER M5 ;
        RECT  7.584 17.088 7.608 17.28 ;
    END
  END i[69]
  PIN i[6]
    DIRECTION INPUT ;
    USE SIGNAL ;
    PORT
      LAYER M3 ;
        RECT  2.664 17.136 2.682 17.28 ;
    END
  END i[6]
  PIN i[70]
    DIRECTION INPUT ;
    USE SIGNAL ;
    PORT
      LAYER M3 ;
        RECT  7.668 17.136 7.686 17.28 ;
    END
  END i[70]
  PIN i[71]
    DIRECTION INPUT ;
    USE SIGNAL ;
    PORT
      LAYER M5 ;
        RECT  7.728 17.088 7.752 17.28 ;
    END
  END i[71]
  PIN i[72]
    DIRECTION INPUT ;
    USE SIGNAL ;
    PORT
      LAYER M3 ;
        RECT  7.812 17.136 7.83 17.28 ;
    END
  END i[72]
  PIN i[73]
    DIRECTION INPUT ;
    USE SIGNAL ;
    PORT
      LAYER M5 ;
        RECT  7.92 17.088 7.944 17.28 ;
    END
  END i[73]
  PIN i[74]
    DIRECTION INPUT ;
    USE SIGNAL ;
    PORT
      LAYER M3 ;
        RECT  7.992 17.136 8.01 17.28 ;
    END
  END i[74]
  PIN i[75]
    DIRECTION INPUT ;
    USE SIGNAL ;
    PORT
      LAYER M5 ;
        RECT  8.064 17.088 8.088 17.28 ;
    END
  END i[75]
  PIN i[76]
    DIRECTION INPUT ;
    USE SIGNAL ;
    PORT
      LAYER M3 ;
        RECT  8.136 17.136 8.154 17.28 ;
    END
  END i[76]
  PIN i[77]
    DIRECTION INPUT ;
    USE SIGNAL ;
    PORT
      LAYER M5 ;
        RECT  8.208 17.088 8.232 17.28 ;
    END
  END i[77]
  PIN i[78]
    DIRECTION INPUT ;
    USE SIGNAL ;
    PORT
      LAYER M3 ;
        RECT  8.28 17.136 8.298 17.28 ;
    END
  END i[78]
  PIN i[79]
    DIRECTION INPUT ;
    USE SIGNAL ;
    PORT
      LAYER M5 ;
        RECT  8.352 17.088 8.376 17.28 ;
    END
  END i[79]
  PIN i[7]
    DIRECTION INPUT ;
    USE SIGNAL ;
    PORT
      LAYER M5 ;
        RECT  2.736 17.088 2.76 17.28 ;
    END
  END i[7]
  PIN i[80]
    DIRECTION INPUT ;
    USE SIGNAL ;
    PORT
      LAYER M3 ;
        RECT  8.46 17.136 8.478 17.28 ;
    END
  END i[80]
  PIN i[81]
    DIRECTION INPUT ;
    USE SIGNAL ;
    PORT
      LAYER M5 ;
        RECT  8.544 17.088 8.568 17.28 ;
    END
  END i[81]
  PIN i[82]
    DIRECTION INPUT ;
    USE SIGNAL ;
    PORT
      LAYER M3 ;
        RECT  8.604 17.136 8.622 17.28 ;
    END
  END i[82]
  PIN i[83]
    DIRECTION INPUT ;
    USE SIGNAL ;
    PORT
      LAYER M5 ;
        RECT  8.688 17.088 8.712 17.28 ;
    END
  END i[83]
  PIN i[84]
    DIRECTION INPUT ;
    USE SIGNAL ;
    PORT
      LAYER M3 ;
        RECT  8.748 17.136 8.766 17.28 ;
    END
  END i[84]
  PIN i[85]
    DIRECTION INPUT ;
    USE SIGNAL ;
    PORT
      LAYER M5 ;
        RECT  8.832 17.088 8.856 17.28 ;
    END
  END i[85]
  PIN i[86]
    DIRECTION INPUT ;
    USE SIGNAL ;
    PORT
      LAYER M3 ;
        RECT  8.928 17.136 8.946 17.28 ;
    END
  END i[86]
  PIN i[87]
    DIRECTION INPUT ;
    USE SIGNAL ;
    PORT
      LAYER M5 ;
        RECT  8.976 17.088 9 17.28 ;
    END
  END i[87]
  PIN i[88]
    DIRECTION INPUT ;
    USE SIGNAL ;
    PORT
      LAYER M3 ;
        RECT  9.072 17.136 9.09 17.28 ;
    END
  END i[88]
  PIN i[89]
    DIRECTION INPUT ;
    USE SIGNAL ;
    PORT
      LAYER M5 ;
        RECT  9.168 17.088 9.192 17.28 ;
    END
  END i[89]
  PIN i[8]
    DIRECTION INPUT ;
    USE SIGNAL ;
    PORT
      LAYER M3 ;
        RECT  2.808 17.136 2.826 17.28 ;
    END
  END i[8]
  PIN i[90]
    DIRECTION INPUT ;
    USE SIGNAL ;
    PORT
      LAYER M3 ;
        RECT  9.216 17.136 9.234 17.28 ;
    END
  END i[90]
  PIN i[91]
    DIRECTION INPUT ;
    USE SIGNAL ;
    PORT
      LAYER M5 ;
        RECT  9.312 17.088 9.336 17.28 ;
    END
  END i[91]
  PIN i[92]
    DIRECTION INPUT ;
    USE SIGNAL ;
    PORT
      LAYER M3 ;
        RECT  9.396 17.136 9.414 17.28 ;
    END
  END i[92]
  PIN i[93]
    DIRECTION INPUT ;
    USE SIGNAL ;
    PORT
      LAYER M5 ;
        RECT  9.456 17.088 9.48 17.28 ;
    END
  END i[93]
  PIN i[94]
    DIRECTION INPUT ;
    USE SIGNAL ;
    PORT
      LAYER M3 ;
        RECT  9.54 17.136 9.558 17.28 ;
    END
  END i[94]
  PIN i[95]
    DIRECTION INPUT ;
    USE SIGNAL ;
    PORT
      LAYER M5 ;
        RECT  9.6 17.088 9.624 17.28 ;
    END
  END i[95]
  PIN i[96]
    DIRECTION INPUT ;
    USE SIGNAL ;
    PORT
      LAYER M3 ;
        RECT  9.72 17.136 9.738 17.28 ;
    END
  END i[96]
  PIN i[97]
    DIRECTION INPUT ;
    USE SIGNAL ;
    PORT
      LAYER M5 ;
        RECT  9.792 17.088 9.816 17.28 ;
    END
  END i[97]
  PIN i[98]
    DIRECTION INPUT ;
    USE SIGNAL ;
    PORT
      LAYER M3 ;
        RECT  9.864 17.136 9.882 17.28 ;
    END
  END i[98]
  PIN i[99]
    DIRECTION INPUT ;
    USE SIGNAL ;
    PORT
      LAYER M5 ;
        RECT  9.936 17.088 9.96 17.28 ;
    END
  END i[99]
  PIN i[9]
    DIRECTION INPUT ;
    USE SIGNAL ;
    PORT
      LAYER M5 ;
        RECT  2.88 17.088 2.904 17.28 ;
    END
  END i[9]
  PIN o[0]
    DIRECTION OUTPUT ;
    USE SIGNAL ;
    PORT
      LAYER M3 ;
        RECT  2.196 0 2.214 0.144 ;
    END
  END o[0]
  PIN o[100]
    DIRECTION OUTPUT ;
    USE SIGNAL ;
    PORT
      LAYER M3 ;
        RECT  9.972 0 9.99 0.144 ;
    END
  END o[100]
  PIN o[101]
    DIRECTION OUTPUT ;
    USE SIGNAL ;
    PORT
      LAYER M5 ;
        RECT  10.08 0 10.104 0.192 ;
    END
  END o[101]
  PIN o[102]
    DIRECTION OUTPUT ;
    USE SIGNAL ;
    PORT
      LAYER M3 ;
        RECT  10.152 0 10.17 0.144 ;
    END
  END o[102]
  PIN o[103]
    DIRECTION OUTPUT ;
    USE SIGNAL ;
    PORT
      LAYER M5 ;
        RECT  10.224 0 10.248 0.192 ;
    END
  END o[103]
  PIN o[104]
    DIRECTION OUTPUT ;
    USE SIGNAL ;
    PORT
      LAYER M3 ;
        RECT  10.296 0 10.314 0.144 ;
    END
  END o[104]
  PIN o[105]
    DIRECTION OUTPUT ;
    USE SIGNAL ;
    PORT
      LAYER M5 ;
        RECT  10.368 0 10.392 0.192 ;
    END
  END o[105]
  PIN o[106]
    DIRECTION OUTPUT ;
    USE SIGNAL ;
    PORT
      LAYER M3 ;
        RECT  10.44 0 10.458 0.144 ;
    END
  END o[106]
  PIN o[107]
    DIRECTION OUTPUT ;
    USE SIGNAL ;
    PORT
      LAYER M5 ;
        RECT  10.512 0 10.536 0.192 ;
    END
  END o[107]
  PIN o[108]
    DIRECTION OUTPUT ;
    USE SIGNAL ;
    PORT
      LAYER M3 ;
        RECT  10.62 0 10.638 0.144 ;
    END
  END o[108]
  PIN o[109]
    DIRECTION OUTPUT ;
    USE SIGNAL ;
    PORT
      LAYER M5 ;
        RECT  10.704 0 10.728 0.192 ;
    END
  END o[109]
  PIN o[10]
    DIRECTION OUTPUT ;
    USE SIGNAL ;
    PORT
      LAYER M3 ;
        RECT  2.952 0 2.97 0.144 ;
    END
  END o[10]
  PIN o[110]
    DIRECTION OUTPUT ;
    USE SIGNAL ;
    PORT
      LAYER M3 ;
        RECT  10.764 0 10.782 0.144 ;
    END
  END o[110]
  PIN o[111]
    DIRECTION OUTPUT ;
    USE SIGNAL ;
    PORT
      LAYER M5 ;
        RECT  10.848 0 10.872 0.192 ;
    END
  END o[111]
  PIN o[112]
    DIRECTION OUTPUT ;
    USE SIGNAL ;
    PORT
      LAYER M3 ;
        RECT  10.908 0 10.926 0.144 ;
    END
  END o[112]
  PIN o[113]
    DIRECTION OUTPUT ;
    USE SIGNAL ;
    PORT
      LAYER M5 ;
        RECT  10.992 0 11.016 0.192 ;
    END
  END o[113]
  PIN o[114]
    DIRECTION OUTPUT ;
    USE SIGNAL ;
    PORT
      LAYER M3 ;
        RECT  11.088 0 11.106 0.144 ;
    END
  END o[114]
  PIN o[115]
    DIRECTION OUTPUT ;
    USE SIGNAL ;
    PORT
      LAYER M5 ;
        RECT  11.136 0 11.16 0.192 ;
    END
  END o[115]
  PIN o[116]
    DIRECTION OUTPUT ;
    USE SIGNAL ;
    PORT
      LAYER M3 ;
        RECT  11.232 0 11.25 0.144 ;
    END
  END o[116]
  PIN o[117]
    DIRECTION OUTPUT ;
    USE SIGNAL ;
    PORT
      LAYER M5 ;
        RECT  11.328 0 11.352 0.192 ;
    END
  END o[117]
  PIN o[118]
    DIRECTION OUTPUT ;
    USE SIGNAL ;
    PORT
      LAYER M3 ;
        RECT  11.376 0 11.394 0.144 ;
    END
  END o[118]
  PIN o[119]
    DIRECTION OUTPUT ;
    USE SIGNAL ;
    PORT
      LAYER M5 ;
        RECT  11.472 0 11.496 0.192 ;
    END
  END o[119]
  PIN o[11]
    DIRECTION OUTPUT ;
    USE SIGNAL ;
    PORT
      LAYER M5 ;
        RECT  3.024 0 3.048 0.192 ;
    END
  END o[11]
  PIN o[120]
    DIRECTION OUTPUT ;
    USE SIGNAL ;
    PORT
      LAYER M3 ;
        RECT  11.556 0 11.574 0.144 ;
    END
  END o[120]
  PIN o[121]
    DIRECTION OUTPUT ;
    USE SIGNAL ;
    PORT
      LAYER M5 ;
        RECT  11.616 0 11.64 0.192 ;
    END
  END o[121]
  PIN o[122]
    DIRECTION OUTPUT ;
    USE SIGNAL ;
    PORT
      LAYER M3 ;
        RECT  11.7 0 11.718 0.144 ;
    END
  END o[122]
  PIN o[123]
    DIRECTION OUTPUT ;
    USE SIGNAL ;
    PORT
      LAYER M5 ;
        RECT  11.76 0 11.784 0.192 ;
    END
  END o[123]
  PIN o[124]
    DIRECTION OUTPUT ;
    USE SIGNAL ;
    PORT
      LAYER M3 ;
        RECT  11.844 0 11.862 0.144 ;
    END
  END o[124]
  PIN o[125]
    DIRECTION OUTPUT ;
    USE SIGNAL ;
    PORT
      LAYER M5 ;
        RECT  11.952 0 11.976 0.192 ;
    END
  END o[125]
  PIN o[126]
    DIRECTION OUTPUT ;
    USE SIGNAL ;
    PORT
      LAYER M3 ;
        RECT  12.024 0 12.042 0.144 ;
    END
  END o[126]
  PIN o[127]
    DIRECTION OUTPUT ;
    USE SIGNAL ;
    PORT
      LAYER M5 ;
        RECT  12.096 0 12.12 0.192 ;
    END
  END o[127]
  PIN o[128]
    DIRECTION OUTPUT ;
    USE SIGNAL ;
    PORT
      LAYER M3 ;
        RECT  12.168 0 12.186 0.144 ;
    END
  END o[128]
  PIN o[129]
    DIRECTION OUTPUT ;
    USE SIGNAL ;
    PORT
      LAYER M5 ;
        RECT  12.24 0 12.264 0.192 ;
    END
  END o[129]
  PIN o[12]
    DIRECTION OUTPUT ;
    USE SIGNAL ;
    PORT
      LAYER M3 ;
        RECT  3.132 0 3.15 0.144 ;
    END
  END o[12]
  PIN o[130]
    DIRECTION OUTPUT ;
    USE SIGNAL ;
    PORT
      LAYER M3 ;
        RECT  12.312 0 12.33 0.144 ;
    END
  END o[130]
  PIN o[131]
    DIRECTION OUTPUT ;
    USE SIGNAL ;
    PORT
      LAYER M5 ;
        RECT  12.384 0 12.408 0.192 ;
    END
  END o[131]
  PIN o[132]
    DIRECTION OUTPUT ;
    USE SIGNAL ;
    PORT
      LAYER M3 ;
        RECT  12.492 0 12.51 0.144 ;
    END
  END o[132]
  PIN o[133]
    DIRECTION OUTPUT ;
    USE SIGNAL ;
    PORT
      LAYER M5 ;
        RECT  12.576 0 12.6 0.192 ;
    END
  END o[133]
  PIN o[134]
    DIRECTION OUTPUT ;
    USE SIGNAL ;
    PORT
      LAYER M3 ;
        RECT  12.636 0 12.654 0.144 ;
    END
  END o[134]
  PIN o[135]
    DIRECTION OUTPUT ;
    USE SIGNAL ;
    PORT
      LAYER M5 ;
        RECT  12.72 0 12.744 0.192 ;
    END
  END o[135]
  PIN o[136]
    DIRECTION OUTPUT ;
    USE SIGNAL ;
    PORT
      LAYER M3 ;
        RECT  12.78 0 12.798 0.144 ;
    END
  END o[136]
  PIN o[137]
    DIRECTION OUTPUT ;
    USE SIGNAL ;
    PORT
      LAYER M5 ;
        RECT  12.864 0 12.888 0.192 ;
    END
  END o[137]
  PIN o[138]
    DIRECTION OUTPUT ;
    USE SIGNAL ;
    PORT
      LAYER M5 ;
        RECT  13.008 0 13.032 0.192 ;
    END
  END o[138]
  PIN o[139]
    DIRECTION OUTPUT ;
    USE SIGNAL ;
    PORT
      LAYER M3 ;
        RECT  13.104 0 13.122 0.144 ;
    END
  END o[139]
  PIN o[13]
    DIRECTION OUTPUT ;
    USE SIGNAL ;
    PORT
      LAYER M5 ;
        RECT  3.216 0 3.24 0.192 ;
    END
  END o[13]
  PIN o[140]
    DIRECTION OUTPUT ;
    USE SIGNAL ;
    PORT
      LAYER M5 ;
        RECT  13.2 0 13.224 0.192 ;
    END
  END o[140]
  PIN o[141]
    DIRECTION OUTPUT ;
    USE SIGNAL ;
    PORT
      LAYER M3 ;
        RECT  13.248 0 13.266 0.144 ;
    END
  END o[141]
  PIN o[142]
    DIRECTION OUTPUT ;
    USE SIGNAL ;
    PORT
      LAYER M5 ;
        RECT  13.344 0 13.368 0.192 ;
    END
  END o[142]
  PIN o[143]
    DIRECTION OUTPUT ;
    USE SIGNAL ;
    PORT
      LAYER M3 ;
        RECT  13.428 0 13.446 0.144 ;
    END
  END o[143]
  PIN o[144]
    DIRECTION OUTPUT ;
    USE SIGNAL ;
    PORT
      LAYER M5 ;
        RECT  13.488 0 13.512 0.192 ;
    END
  END o[144]
  PIN o[145]
    DIRECTION OUTPUT ;
    USE SIGNAL ;
    PORT
      LAYER M3 ;
        RECT  13.572 0 13.59 0.144 ;
    END
  END o[145]
  PIN o[146]
    DIRECTION OUTPUT ;
    USE SIGNAL ;
    PORT
      LAYER M5 ;
        RECT  13.632 0 13.656 0.192 ;
    END
  END o[146]
  PIN o[147]
    DIRECTION OUTPUT ;
    USE SIGNAL ;
    PORT
      LAYER M3 ;
        RECT  13.716 0 13.734 0.144 ;
    END
  END o[147]
  PIN o[148]
    DIRECTION OUTPUT ;
    USE SIGNAL ;
    PORT
      LAYER M5 ;
        RECT  13.824 0 13.848 0.192 ;
    END
  END o[148]
  PIN o[149]
    DIRECTION OUTPUT ;
    USE SIGNAL ;
    PORT
      LAYER M3 ;
        RECT  13.896 0 13.914 0.144 ;
    END
  END o[149]
  PIN o[14]
    DIRECTION OUTPUT ;
    USE SIGNAL ;
    PORT
      LAYER M3 ;
        RECT  3.276 0 3.294 0.144 ;
    END
  END o[14]
  PIN o[150]
    DIRECTION OUTPUT ;
    USE SIGNAL ;
    PORT
      LAYER M5 ;
        RECT  13.968 0 13.992 0.192 ;
    END
  END o[150]
  PIN o[151]
    DIRECTION OUTPUT ;
    USE SIGNAL ;
    PORT
      LAYER M3 ;
        RECT  14.04 0 14.058 0.144 ;
    END
  END o[151]
  PIN o[152]
    DIRECTION OUTPUT ;
    USE SIGNAL ;
    PORT
      LAYER M5 ;
        RECT  14.112 0 14.136 0.192 ;
    END
  END o[152]
  PIN o[153]
    DIRECTION OUTPUT ;
    USE SIGNAL ;
    PORT
      LAYER M3 ;
        RECT  14.184 0 14.202 0.144 ;
    END
  END o[153]
  PIN o[154]
    DIRECTION OUTPUT ;
    USE SIGNAL ;
    PORT
      LAYER M5 ;
        RECT  14.256 0 14.28 0.192 ;
    END
  END o[154]
  PIN o[155]
    DIRECTION OUTPUT ;
    USE SIGNAL ;
    PORT
      LAYER M3 ;
        RECT  14.364 0 14.382 0.144 ;
    END
  END o[155]
  PIN o[156]
    DIRECTION OUTPUT ;
    USE SIGNAL ;
    PORT
      LAYER M5 ;
        RECT  14.448 0 14.472 0.192 ;
    END
  END o[156]
  PIN o[157]
    DIRECTION OUTPUT ;
    USE SIGNAL ;
    PORT
      LAYER M3 ;
        RECT  14.508 0 14.526 0.144 ;
    END
  END o[157]
  PIN o[158]
    DIRECTION OUTPUT ;
    USE SIGNAL ;
    PORT
      LAYER M5 ;
        RECT  14.592 0 14.616 0.192 ;
    END
  END o[158]
  PIN o[159]
    DIRECTION OUTPUT ;
    USE SIGNAL ;
    PORT
      LAYER M3 ;
        RECT  14.652 0 14.67 0.144 ;
    END
  END o[159]
  PIN o[15]
    DIRECTION OUTPUT ;
    USE SIGNAL ;
    PORT
      LAYER M5 ;
        RECT  3.36 0 3.384 0.192 ;
    END
  END o[15]
  PIN o[160]
    DIRECTION OUTPUT ;
    USE SIGNAL ;
    PORT
      LAYER M5 ;
        RECT  14.736 0 14.76 0.192 ;
    END
  END o[160]
  PIN o[161]
    DIRECTION OUTPUT ;
    USE SIGNAL ;
    PORT
      LAYER M3 ;
        RECT  14.832 0 14.85 0.144 ;
    END
  END o[161]
  PIN o[162]
    DIRECTION OUTPUT ;
    USE SIGNAL ;
    PORT
      LAYER M5 ;
        RECT  14.88 0 14.904 0.192 ;
    END
  END o[162]
  PIN o[163]
    DIRECTION OUTPUT ;
    USE SIGNAL ;
    PORT
      LAYER M3 ;
        RECT  14.976 0 14.994 0.144 ;
    END
  END o[163]
  PIN o[164]
    DIRECTION OUTPUT ;
    USE SIGNAL ;
    PORT
      LAYER M5 ;
        RECT  15.072 0 15.096 0.192 ;
    END
  END o[164]
  PIN o[165]
    DIRECTION OUTPUT ;
    USE SIGNAL ;
    PORT
      LAYER M3 ;
        RECT  15.12 0 15.138 0.144 ;
    END
  END o[165]
  PIN o[166]
    DIRECTION OUTPUT ;
    USE SIGNAL ;
    PORT
      LAYER M5 ;
        RECT  15.216 0 15.24 0.192 ;
    END
  END o[166]
  PIN o[167]
    DIRECTION OUTPUT ;
    USE SIGNAL ;
    PORT
      LAYER M3 ;
        RECT  15.3 0 15.318 0.144 ;
    END
  END o[167]
  PIN o[168]
    DIRECTION OUTPUT ;
    USE SIGNAL ;
    PORT
      LAYER M5 ;
        RECT  15.36 0 15.384 0.192 ;
    END
  END o[168]
  PIN o[169]
    DIRECTION OUTPUT ;
    USE SIGNAL ;
    PORT
      LAYER M3 ;
        RECT  15.444 0 15.462 0.144 ;
    END
  END o[169]
  PIN o[16]
    DIRECTION OUTPUT ;
    USE SIGNAL ;
    PORT
      LAYER M3 ;
        RECT  3.42 0 3.438 0.144 ;
    END
  END o[16]
  PIN o[170]
    DIRECTION OUTPUT ;
    USE SIGNAL ;
    PORT
      LAYER M5 ;
        RECT  15.504 0 15.528 0.192 ;
    END
  END o[170]
  PIN o[171]
    DIRECTION OUTPUT ;
    USE SIGNAL ;
    PORT
      LAYER M3 ;
        RECT  15.588 0 15.606 0.144 ;
    END
  END o[171]
  PIN o[172]
    DIRECTION OUTPUT ;
    USE SIGNAL ;
    PORT
      LAYER M5 ;
        RECT  15.696 0 15.72 0.192 ;
    END
  END o[172]
  PIN o[173]
    DIRECTION OUTPUT ;
    USE SIGNAL ;
    PORT
      LAYER M3 ;
        RECT  15.768 0 15.786 0.144 ;
    END
  END o[173]
  PIN o[174]
    DIRECTION OUTPUT ;
    USE SIGNAL ;
    PORT
      LAYER M5 ;
        RECT  15.84 0 15.864 0.192 ;
    END
  END o[174]
  PIN o[175]
    DIRECTION OUTPUT ;
    USE SIGNAL ;
    PORT
      LAYER M3 ;
        RECT  15.912 0 15.93 0.144 ;
    END
  END o[175]
  PIN o[176]
    DIRECTION OUTPUT ;
    USE SIGNAL ;
    PORT
      LAYER M5 ;
        RECT  15.984 0 16.008 0.192 ;
    END
  END o[176]
  PIN o[177]
    DIRECTION OUTPUT ;
    USE SIGNAL ;
    PORT
      LAYER M3 ;
        RECT  16.056 0 16.074 0.144 ;
    END
  END o[177]
  PIN o[178]
    DIRECTION OUTPUT ;
    USE SIGNAL ;
    PORT
      LAYER M5 ;
        RECT  16.128 0 16.152 0.192 ;
    END
  END o[178]
  PIN o[179]
    DIRECTION OUTPUT ;
    USE SIGNAL ;
    PORT
      LAYER M3 ;
        RECT  16.236 0 16.254 0.144 ;
    END
  END o[179]
  PIN o[17]
    DIRECTION OUTPUT ;
    USE SIGNAL ;
    PORT
      LAYER M5 ;
        RECT  3.504 0 3.528 0.192 ;
    END
  END o[17]
  PIN o[180]
    DIRECTION OUTPUT ;
    USE SIGNAL ;
    PORT
      LAYER M5 ;
        RECT  16.32 0 16.344 0.192 ;
    END
  END o[180]
  PIN o[181]
    DIRECTION OUTPUT ;
    USE SIGNAL ;
    PORT
      LAYER M3 ;
        RECT  16.38 0 16.398 0.144 ;
    END
  END o[181]
  PIN o[182]
    DIRECTION OUTPUT ;
    USE SIGNAL ;
    PORT
      LAYER M5 ;
        RECT  16.464 0 16.488 0.192 ;
    END
  END o[182]
  PIN o[183]
    DIRECTION OUTPUT ;
    USE SIGNAL ;
    PORT
      LAYER M3 ;
        RECT  16.524 0 16.542 0.144 ;
    END
  END o[183]
  PIN o[184]
    DIRECTION OUTPUT ;
    USE SIGNAL ;
    PORT
      LAYER M5 ;
        RECT  16.608 0 16.632 0.192 ;
    END
  END o[184]
  PIN o[185]
    DIRECTION OUTPUT ;
    USE SIGNAL ;
    PORT
      LAYER M3 ;
        RECT  16.704 0 16.722 0.144 ;
    END
  END o[185]
  PIN o[186]
    DIRECTION OUTPUT ;
    USE SIGNAL ;
    PORT
      LAYER M5 ;
        RECT  16.752 0 16.776 0.192 ;
    END
  END o[186]
  PIN o[187]
    DIRECTION OUTPUT ;
    USE SIGNAL ;
    PORT
      LAYER M3 ;
        RECT  16.848 0 16.866 0.144 ;
    END
  END o[187]
  PIN o[188]
    DIRECTION OUTPUT ;
    USE SIGNAL ;
    PORT
      LAYER M5 ;
        RECT  16.944 0 16.968 0.192 ;
    END
  END o[188]
  PIN o[189]
    DIRECTION OUTPUT ;
    USE SIGNAL ;
    PORT
      LAYER M3 ;
        RECT  16.992 0 17.01 0.144 ;
    END
  END o[189]
  PIN o[18]
    DIRECTION OUTPUT ;
    USE SIGNAL ;
    PORT
      LAYER M3 ;
        RECT  3.6 0 3.618 0.144 ;
    END
  END o[18]
  PIN o[190]
    DIRECTION OUTPUT ;
    USE SIGNAL ;
    PORT
      LAYER M5 ;
        RECT  17.088 0 17.112 0.192 ;
    END
  END o[190]
  PIN o[191]
    DIRECTION OUTPUT ;
    USE SIGNAL ;
    PORT
      LAYER M3 ;
        RECT  17.172 0 17.19 0.144 ;
    END
  END o[191]
  PIN o[192]
    DIRECTION OUTPUT ;
    USE SIGNAL ;
    PORT
      LAYER M5 ;
        RECT  17.232 0 17.256 0.192 ;
    END
  END o[192]
  PIN o[193]
    DIRECTION OUTPUT ;
    USE SIGNAL ;
    PORT
      LAYER M3 ;
        RECT  17.316 0 17.334 0.144 ;
    END
  END o[193]
  PIN o[194]
    DIRECTION OUTPUT ;
    USE SIGNAL ;
    PORT
      LAYER M5 ;
        RECT  17.376 0 17.4 0.192 ;
    END
  END o[194]
  PIN o[195]
    DIRECTION OUTPUT ;
    USE SIGNAL ;
    PORT
      LAYER M3 ;
        RECT  17.46 0 17.478 0.144 ;
    END
  END o[195]
  PIN o[196]
    DIRECTION OUTPUT ;
    USE SIGNAL ;
    PORT
      LAYER M5 ;
        RECT  17.568 0 17.592 0.192 ;
    END
  END o[196]
  PIN o[197]
    DIRECTION OUTPUT ;
    USE SIGNAL ;
    PORT
      LAYER M3 ;
        RECT  17.64 0 17.658 0.144 ;
    END
  END o[197]
  PIN o[198]
    DIRECTION OUTPUT ;
    USE SIGNAL ;
    PORT
      LAYER M5 ;
        RECT  17.712 0 17.736 0.192 ;
    END
  END o[198]
  PIN o[199]
    DIRECTION OUTPUT ;
    USE SIGNAL ;
    PORT
      LAYER M3 ;
        RECT  17.784 0 17.802 0.144 ;
    END
  END o[199]
  PIN o[19]
    DIRECTION OUTPUT ;
    USE SIGNAL ;
    PORT
      LAYER M5 ;
        RECT  3.648 0 3.672 0.192 ;
    END
  END o[19]
  PIN o[1]
    DIRECTION OUTPUT ;
    USE SIGNAL ;
    PORT
      LAYER M5 ;
        RECT  2.256 0 2.28 0.192 ;
    END
  END o[1]
  PIN o[200]
    DIRECTION OUTPUT ;
    USE SIGNAL ;
    PORT
      LAYER M5 ;
        RECT  17.856 0 17.88 0.192 ;
    END
  END o[200]
  PIN o[201]
    DIRECTION OUTPUT ;
    USE SIGNAL ;
    PORT
      LAYER M3 ;
        RECT  17.928 0 17.946 0.144 ;
    END
  END o[201]
  PIN o[202]
    DIRECTION OUTPUT ;
    USE SIGNAL ;
    PORT
      LAYER M5 ;
        RECT  18 0 18.024 0.192 ;
    END
  END o[202]
  PIN o[203]
    DIRECTION OUTPUT ;
    USE SIGNAL ;
    PORT
      LAYER M3 ;
        RECT  18.108 0 18.126 0.144 ;
    END
  END o[203]
  PIN o[204]
    DIRECTION OUTPUT ;
    USE SIGNAL ;
    PORT
      LAYER M5 ;
        RECT  18.192 0 18.216 0.192 ;
    END
  END o[204]
  PIN o[205]
    DIRECTION OUTPUT ;
    USE SIGNAL ;
    PORT
      LAYER M3 ;
        RECT  18.252 0 18.27 0.144 ;
    END
  END o[205]
  PIN o[206]
    DIRECTION OUTPUT ;
    USE SIGNAL ;
    PORT
      LAYER M5 ;
        RECT  18.336 0 18.36 0.192 ;
    END
  END o[206]
  PIN o[207]
    DIRECTION OUTPUT ;
    USE SIGNAL ;
    PORT
      LAYER M3 ;
        RECT  18.396 0 18.414 0.144 ;
    END
  END o[207]
  PIN o[208]
    DIRECTION OUTPUT ;
    USE SIGNAL ;
    PORT
      LAYER M5 ;
        RECT  18.48 0 18.504 0.192 ;
    END
  END o[208]
  PIN o[209]
    DIRECTION OUTPUT ;
    USE SIGNAL ;
    PORT
      LAYER M3 ;
        RECT  18.576 0 18.594 0.144 ;
    END
  END o[209]
  PIN o[20]
    DIRECTION OUTPUT ;
    USE SIGNAL ;
    PORT
      LAYER M3 ;
        RECT  3.744 0 3.762 0.144 ;
    END
  END o[20]
  PIN o[210]
    DIRECTION OUTPUT ;
    USE SIGNAL ;
    PORT
      LAYER M5 ;
        RECT  18.624 0 18.648 0.192 ;
    END
  END o[210]
  PIN o[211]
    DIRECTION OUTPUT ;
    USE SIGNAL ;
    PORT
      LAYER M3 ;
        RECT  18.72 0 18.738 0.144 ;
    END
  END o[211]
  PIN o[212]
    DIRECTION OUTPUT ;
    USE SIGNAL ;
    PORT
      LAYER M5 ;
        RECT  18.816 0 18.84 0.192 ;
    END
  END o[212]
  PIN o[213]
    DIRECTION OUTPUT ;
    USE SIGNAL ;
    PORT
      LAYER M3 ;
        RECT  18.864 0 18.882 0.144 ;
    END
  END o[213]
  PIN o[214]
    DIRECTION OUTPUT ;
    USE SIGNAL ;
    PORT
      LAYER M5 ;
        RECT  18.96 0 18.984 0.192 ;
    END
  END o[214]
  PIN o[215]
    DIRECTION OUTPUT ;
    USE SIGNAL ;
    PORT
      LAYER M3 ;
        RECT  19.044 0 19.062 0.144 ;
    END
  END o[215]
  PIN o[216]
    DIRECTION OUTPUT ;
    USE SIGNAL ;
    PORT
      LAYER M5 ;
        RECT  19.104 0 19.128 0.192 ;
    END
  END o[216]
  PIN o[217]
    DIRECTION OUTPUT ;
    USE SIGNAL ;
    PORT
      LAYER M3 ;
        RECT  19.188 0 19.206 0.144 ;
    END
  END o[217]
  PIN o[218]
    DIRECTION OUTPUT ;
    USE SIGNAL ;
    PORT
      LAYER M5 ;
        RECT  19.248 0 19.272 0.192 ;
    END
  END o[218]
  PIN o[219]
    DIRECTION OUTPUT ;
    USE SIGNAL ;
    PORT
      LAYER M3 ;
        RECT  19.332 0 19.35 0.144 ;
    END
  END o[219]
  PIN o[21]
    DIRECTION OUTPUT ;
    USE SIGNAL ;
    PORT
      LAYER M5 ;
        RECT  3.84 0 3.864 0.192 ;
    END
  END o[21]
  PIN o[220]
    DIRECTION OUTPUT ;
    USE SIGNAL ;
    PORT
      LAYER M5 ;
        RECT  19.44 0 19.464 0.192 ;
    END
  END o[220]
  PIN o[221]
    DIRECTION OUTPUT ;
    USE SIGNAL ;
    PORT
      LAYER M3 ;
        RECT  19.512 0 19.53 0.144 ;
    END
  END o[221]
  PIN o[222]
    DIRECTION OUTPUT ;
    USE SIGNAL ;
    PORT
      LAYER M5 ;
        RECT  19.584 0 19.608 0.192 ;
    END
  END o[222]
  PIN o[223]
    DIRECTION OUTPUT ;
    USE SIGNAL ;
    PORT
      LAYER M3 ;
        RECT  19.656 0 19.674 0.144 ;
    END
  END o[223]
  PIN o[224]
    DIRECTION OUTPUT ;
    USE SIGNAL ;
    PORT
      LAYER M5 ;
        RECT  19.728 0 19.752 0.192 ;
    END
  END o[224]
  PIN o[225]
    DIRECTION OUTPUT ;
    USE SIGNAL ;
    PORT
      LAYER M3 ;
        RECT  19.8 0 19.818 0.144 ;
    END
  END o[225]
  PIN o[226]
    DIRECTION OUTPUT ;
    USE SIGNAL ;
    PORT
      LAYER M5 ;
        RECT  19.872 0 19.896 0.192 ;
    END
  END o[226]
  PIN o[227]
    DIRECTION OUTPUT ;
    USE SIGNAL ;
    PORT
      LAYER M3 ;
        RECT  19.98 0 19.998 0.144 ;
    END
  END o[227]
  PIN o[228]
    DIRECTION OUTPUT ;
    USE SIGNAL ;
    PORT
      LAYER M5 ;
        RECT  20.064 0 20.088 0.192 ;
    END
  END o[228]
  PIN o[229]
    DIRECTION OUTPUT ;
    USE SIGNAL ;
    PORT
      LAYER M3 ;
        RECT  20.124 0 20.142 0.144 ;
    END
  END o[229]
  PIN o[22]
    DIRECTION OUTPUT ;
    USE SIGNAL ;
    PORT
      LAYER M3 ;
        RECT  3.888 0 3.906 0.144 ;
    END
  END o[22]
  PIN o[230]
    DIRECTION OUTPUT ;
    USE SIGNAL ;
    PORT
      LAYER M5 ;
        RECT  20.208 0 20.232 0.192 ;
    END
  END o[230]
  PIN o[231]
    DIRECTION OUTPUT ;
    USE SIGNAL ;
    PORT
      LAYER M3 ;
        RECT  20.268 0 20.286 0.144 ;
    END
  END o[231]
  PIN o[232]
    DIRECTION OUTPUT ;
    USE SIGNAL ;
    PORT
      LAYER M5 ;
        RECT  20.352 0 20.376 0.192 ;
    END
  END o[232]
  PIN o[233]
    DIRECTION OUTPUT ;
    USE SIGNAL ;
    PORT
      LAYER M3 ;
        RECT  20.448 0 20.466 0.144 ;
    END
  END o[233]
  PIN o[234]
    DIRECTION OUTPUT ;
    USE SIGNAL ;
    PORT
      LAYER M5 ;
        RECT  20.496 0 20.52 0.192 ;
    END
  END o[234]
  PIN o[235]
    DIRECTION OUTPUT ;
    USE SIGNAL ;
    PORT
      LAYER M3 ;
        RECT  20.592 0 20.61 0.144 ;
    END
  END o[235]
  PIN o[236]
    DIRECTION OUTPUT ;
    USE SIGNAL ;
    PORT
      LAYER M5 ;
        RECT  20.688 0 20.712 0.192 ;
    END
  END o[236]
  PIN o[237]
    DIRECTION OUTPUT ;
    USE SIGNAL ;
    PORT
      LAYER M3 ;
        RECT  20.736 0 20.754 0.144 ;
    END
  END o[237]
  PIN o[238]
    DIRECTION OUTPUT ;
    USE SIGNAL ;
    PORT
      LAYER M5 ;
        RECT  20.832 0 20.856 0.192 ;
    END
  END o[238]
  PIN o[239]
    DIRECTION OUTPUT ;
    USE SIGNAL ;
    PORT
      LAYER M3 ;
        RECT  20.916 0 20.934 0.144 ;
    END
  END o[239]
  PIN o[23]
    DIRECTION OUTPUT ;
    USE SIGNAL ;
    PORT
      LAYER M5 ;
        RECT  3.984 0 4.008 0.192 ;
    END
  END o[23]
  PIN o[240]
    DIRECTION OUTPUT ;
    USE SIGNAL ;
    PORT
      LAYER M5 ;
        RECT  20.976 0 21 0.192 ;
    END
  END o[240]
  PIN o[241]
    DIRECTION OUTPUT ;
    USE SIGNAL ;
    PORT
      LAYER M3 ;
        RECT  21.06 0 21.078 0.144 ;
    END
  END o[241]
  PIN o[242]
    DIRECTION OUTPUT ;
    USE SIGNAL ;
    PORT
      LAYER M5 ;
        RECT  21.12 0 21.144 0.192 ;
    END
  END o[242]
  PIN o[243]
    DIRECTION OUTPUT ;
    USE SIGNAL ;
    PORT
      LAYER M3 ;
        RECT  21.204 0 21.222 0.144 ;
    END
  END o[243]
  PIN o[244]
    DIRECTION OUTPUT ;
    USE SIGNAL ;
    PORT
      LAYER M5 ;
        RECT  21.312 0 21.336 0.192 ;
    END
  END o[244]
  PIN o[245]
    DIRECTION OUTPUT ;
    USE SIGNAL ;
    PORT
      LAYER M3 ;
        RECT  21.384 0 21.402 0.144 ;
    END
  END o[245]
  PIN o[246]
    DIRECTION OUTPUT ;
    USE SIGNAL ;
    PORT
      LAYER M5 ;
        RECT  21.456 0 21.48 0.192 ;
    END
  END o[246]
  PIN o[247]
    DIRECTION OUTPUT ;
    USE SIGNAL ;
    PORT
      LAYER M3 ;
        RECT  21.528 0 21.546 0.144 ;
    END
  END o[247]
  PIN o[248]
    DIRECTION OUTPUT ;
    USE SIGNAL ;
    PORT
      LAYER M5 ;
        RECT  21.6 0 21.624 0.192 ;
    END
  END o[248]
  PIN o[249]
    DIRECTION OUTPUT ;
    USE SIGNAL ;
    PORT
      LAYER M3 ;
        RECT  21.672 0 21.69 0.144 ;
    END
  END o[249]
  PIN o[24]
    DIRECTION OUTPUT ;
    USE SIGNAL ;
    PORT
      LAYER M3 ;
        RECT  4.068 0 4.086 0.144 ;
    END
  END o[24]
  PIN o[250]
    DIRECTION OUTPUT ;
    USE SIGNAL ;
    PORT
      LAYER M5 ;
        RECT  21.744 0 21.768 0.192 ;
    END
  END o[250]
  PIN o[251]
    DIRECTION OUTPUT ;
    USE SIGNAL ;
    PORT
      LAYER M3 ;
        RECT  21.852 0 21.87 0.144 ;
    END
  END o[251]
  PIN o[252]
    DIRECTION OUTPUT ;
    USE SIGNAL ;
    PORT
      LAYER M5 ;
        RECT  21.936 0 21.96 0.192 ;
    END
  END o[252]
  PIN o[253]
    DIRECTION OUTPUT ;
    USE SIGNAL ;
    PORT
      LAYER M3 ;
        RECT  21.996 0 22.014 0.144 ;
    END
  END o[253]
  PIN o[254]
    DIRECTION OUTPUT ;
    USE SIGNAL ;
    PORT
      LAYER M5 ;
        RECT  22.08 0 22.104 0.192 ;
    END
  END o[254]
  PIN o[255]
    DIRECTION OUTPUT ;
    USE SIGNAL ;
    PORT
      LAYER M3 ;
        RECT  22.14 0 22.158 0.144 ;
    END
  END o[255]
  PIN o[256]
    DIRECTION OUTPUT ;
    USE SIGNAL ;
    PORT
      LAYER M5 ;
        RECT  22.224 0 22.248 0.192 ;
    END
  END o[256]
  PIN o[257]
    DIRECTION OUTPUT ;
    USE SIGNAL ;
    PORT
      LAYER M3 ;
        RECT  22.32 0 22.338 0.144 ;
    END
  END o[257]
  PIN o[258]
    DIRECTION OUTPUT ;
    USE SIGNAL ;
    PORT
      LAYER M5 ;
        RECT  22.368 0 22.392 0.192 ;
    END
  END o[258]
  PIN o[259]
    DIRECTION OUTPUT ;
    USE SIGNAL ;
    PORT
      LAYER M3 ;
        RECT  22.464 0 22.482 0.144 ;
    END
  END o[259]
  PIN o[25]
    DIRECTION OUTPUT ;
    USE SIGNAL ;
    PORT
      LAYER M5 ;
        RECT  4.128 0 4.152 0.192 ;
    END
  END o[25]
  PIN o[260]
    DIRECTION OUTPUT ;
    USE SIGNAL ;
    PORT
      LAYER M5 ;
        RECT  22.56 0 22.584 0.192 ;
    END
  END o[260]
  PIN o[261]
    DIRECTION OUTPUT ;
    USE SIGNAL ;
    PORT
      LAYER M3 ;
        RECT  22.608 0 22.626 0.144 ;
    END
  END o[261]
  PIN o[262]
    DIRECTION OUTPUT ;
    USE SIGNAL ;
    PORT
      LAYER M5 ;
        RECT  22.704 0 22.728 0.192 ;
    END
  END o[262]
  PIN o[263]
    DIRECTION OUTPUT ;
    USE SIGNAL ;
    PORT
      LAYER M3 ;
        RECT  22.788 0 22.806 0.144 ;
    END
  END o[263]
  PIN o[264]
    DIRECTION OUTPUT ;
    USE SIGNAL ;
    PORT
      LAYER M5 ;
        RECT  22.848 0 22.872 0.192 ;
    END
  END o[264]
  PIN o[265]
    DIRECTION OUTPUT ;
    USE SIGNAL ;
    PORT
      LAYER M3 ;
        RECT  22.932 0 22.95 0.144 ;
    END
  END o[265]
  PIN o[266]
    DIRECTION OUTPUT ;
    USE SIGNAL ;
    PORT
      LAYER M5 ;
        RECT  22.992 0 23.016 0.192 ;
    END
  END o[266]
  PIN o[267]
    DIRECTION OUTPUT ;
    USE SIGNAL ;
    PORT
      LAYER M3 ;
        RECT  23.076 0 23.094 0.144 ;
    END
  END o[267]
  PIN o[268]
    DIRECTION OUTPUT ;
    USE SIGNAL ;
    PORT
      LAYER M5 ;
        RECT  23.184 0 23.208 0.192 ;
    END
  END o[268]
  PIN o[269]
    DIRECTION OUTPUT ;
    USE SIGNAL ;
    PORT
      LAYER M3 ;
        RECT  23.256 0 23.274 0.144 ;
    END
  END o[269]
  PIN o[26]
    DIRECTION OUTPUT ;
    USE SIGNAL ;
    PORT
      LAYER M3 ;
        RECT  4.212 0 4.23 0.144 ;
    END
  END o[26]
  PIN o[270]
    DIRECTION OUTPUT ;
    USE SIGNAL ;
    PORT
      LAYER M5 ;
        RECT  23.328 0 23.352 0.192 ;
    END
  END o[270]
  PIN o[271]
    DIRECTION OUTPUT ;
    USE SIGNAL ;
    PORT
      LAYER M3 ;
        RECT  23.4 0 23.418 0.144 ;
    END
  END o[271]
  PIN o[272]
    DIRECTION OUTPUT ;
    USE SIGNAL ;
    PORT
      LAYER M5 ;
        RECT  23.472 0 23.496 0.192 ;
    END
  END o[272]
  PIN o[273]
    DIRECTION OUTPUT ;
    USE SIGNAL ;
    PORT
      LAYER M3 ;
        RECT  23.544 0 23.562 0.144 ;
    END
  END o[273]
  PIN o[274]
    DIRECTION OUTPUT ;
    USE SIGNAL ;
    PORT
      LAYER M5 ;
        RECT  23.616 0 23.64 0.192 ;
    END
  END o[274]
  PIN o[275]
    DIRECTION OUTPUT ;
    USE SIGNAL ;
    PORT
      LAYER M3 ;
        RECT  23.724 0 23.742 0.144 ;
    END
  END o[275]
  PIN o[27]
    DIRECTION OUTPUT ;
    USE SIGNAL ;
    PORT
      LAYER M5 ;
        RECT  4.272 0 4.296 0.192 ;
    END
  END o[27]
  PIN o[28]
    DIRECTION OUTPUT ;
    USE SIGNAL ;
    PORT
      LAYER M3 ;
        RECT  4.356 0 4.374 0.144 ;
    END
  END o[28]
  PIN o[29]
    DIRECTION OUTPUT ;
    USE SIGNAL ;
    PORT
      LAYER M5 ;
        RECT  4.464 0 4.488 0.192 ;
    END
  END o[29]
  PIN o[2]
    DIRECTION OUTPUT ;
    USE SIGNAL ;
    PORT
      LAYER M3 ;
        RECT  2.34 0 2.358 0.144 ;
    END
  END o[2]
  PIN o[30]
    DIRECTION OUTPUT ;
    USE SIGNAL ;
    PORT
      LAYER M3 ;
        RECT  4.536 0 4.554 0.144 ;
    END
  END o[30]
  PIN o[31]
    DIRECTION OUTPUT ;
    USE SIGNAL ;
    PORT
      LAYER M5 ;
        RECT  4.608 0 4.632 0.192 ;
    END
  END o[31]
  PIN o[32]
    DIRECTION OUTPUT ;
    USE SIGNAL ;
    PORT
      LAYER M3 ;
        RECT  4.68 0 4.698 0.144 ;
    END
  END o[32]
  PIN o[33]
    DIRECTION OUTPUT ;
    USE SIGNAL ;
    PORT
      LAYER M5 ;
        RECT  4.752 0 4.776 0.192 ;
    END
  END o[33]
  PIN o[34]
    DIRECTION OUTPUT ;
    USE SIGNAL ;
    PORT
      LAYER M3 ;
        RECT  4.824 0 4.842 0.144 ;
    END
  END o[34]
  PIN o[35]
    DIRECTION OUTPUT ;
    USE SIGNAL ;
    PORT
      LAYER M5 ;
        RECT  4.896 0 4.92 0.192 ;
    END
  END o[35]
  PIN o[36]
    DIRECTION OUTPUT ;
    USE SIGNAL ;
    PORT
      LAYER M3 ;
        RECT  5.004 0 5.022 0.144 ;
    END
  END o[36]
  PIN o[37]
    DIRECTION OUTPUT ;
    USE SIGNAL ;
    PORT
      LAYER M5 ;
        RECT  5.088 0 5.112 0.192 ;
    END
  END o[37]
  PIN o[38]
    DIRECTION OUTPUT ;
    USE SIGNAL ;
    PORT
      LAYER M3 ;
        RECT  5.148 0 5.166 0.144 ;
    END
  END o[38]
  PIN o[39]
    DIRECTION OUTPUT ;
    USE SIGNAL ;
    PORT
      LAYER M5 ;
        RECT  5.232 0 5.256 0.192 ;
    END
  END o[39]
  PIN o[3]
    DIRECTION OUTPUT ;
    USE SIGNAL ;
    PORT
      LAYER M5 ;
        RECT  2.4 0 2.424 0.192 ;
    END
  END o[3]
  PIN o[40]
    DIRECTION OUTPUT ;
    USE SIGNAL ;
    PORT
      LAYER M3 ;
        RECT  5.292 0 5.31 0.144 ;
    END
  END o[40]
  PIN o[41]
    DIRECTION OUTPUT ;
    USE SIGNAL ;
    PORT
      LAYER M5 ;
        RECT  5.376 0 5.4 0.192 ;
    END
  END o[41]
  PIN o[42]
    DIRECTION OUTPUT ;
    USE SIGNAL ;
    PORT
      LAYER M3 ;
        RECT  5.472 0 5.49 0.144 ;
    END
  END o[42]
  PIN o[43]
    DIRECTION OUTPUT ;
    USE SIGNAL ;
    PORT
      LAYER M5 ;
        RECT  5.52 0 5.544 0.192 ;
    END
  END o[43]
  PIN o[44]
    DIRECTION OUTPUT ;
    USE SIGNAL ;
    PORT
      LAYER M3 ;
        RECT  5.616 0 5.634 0.144 ;
    END
  END o[44]
  PIN o[45]
    DIRECTION OUTPUT ;
    USE SIGNAL ;
    PORT
      LAYER M5 ;
        RECT  5.712 0 5.736 0.192 ;
    END
  END o[45]
  PIN o[46]
    DIRECTION OUTPUT ;
    USE SIGNAL ;
    PORT
      LAYER M3 ;
        RECT  5.76 0 5.778 0.144 ;
    END
  END o[46]
  PIN o[47]
    DIRECTION OUTPUT ;
    USE SIGNAL ;
    PORT
      LAYER M5 ;
        RECT  5.856 0 5.88 0.192 ;
    END
  END o[47]
  PIN o[48]
    DIRECTION OUTPUT ;
    USE SIGNAL ;
    PORT
      LAYER M3 ;
        RECT  5.94 0 5.958 0.144 ;
    END
  END o[48]
  PIN o[49]
    DIRECTION OUTPUT ;
    USE SIGNAL ;
    PORT
      LAYER M5 ;
        RECT  6 0 6.024 0.192 ;
    END
  END o[49]
  PIN o[4]
    DIRECTION OUTPUT ;
    USE SIGNAL ;
    PORT
      LAYER M3 ;
        RECT  2.484 0 2.502 0.144 ;
    END
  END o[4]
  PIN o[50]
    DIRECTION OUTPUT ;
    USE SIGNAL ;
    PORT
      LAYER M3 ;
        RECT  6.084 0 6.102 0.144 ;
    END
  END o[50]
  PIN o[51]
    DIRECTION OUTPUT ;
    USE SIGNAL ;
    PORT
      LAYER M5 ;
        RECT  6.144 0 6.168 0.192 ;
    END
  END o[51]
  PIN o[52]
    DIRECTION OUTPUT ;
    USE SIGNAL ;
    PORT
      LAYER M3 ;
        RECT  6.228 0 6.246 0.144 ;
    END
  END o[52]
  PIN o[53]
    DIRECTION OUTPUT ;
    USE SIGNAL ;
    PORT
      LAYER M5 ;
        RECT  6.336 0 6.36 0.192 ;
    END
  END o[53]
  PIN o[54]
    DIRECTION OUTPUT ;
    USE SIGNAL ;
    PORT
      LAYER M3 ;
        RECT  6.408 0 6.426 0.144 ;
    END
  END o[54]
  PIN o[55]
    DIRECTION OUTPUT ;
    USE SIGNAL ;
    PORT
      LAYER M5 ;
        RECT  6.48 0 6.504 0.192 ;
    END
  END o[55]
  PIN o[56]
    DIRECTION OUTPUT ;
    USE SIGNAL ;
    PORT
      LAYER M3 ;
        RECT  6.552 0 6.57 0.144 ;
    END
  END o[56]
  PIN o[57]
    DIRECTION OUTPUT ;
    USE SIGNAL ;
    PORT
      LAYER M5 ;
        RECT  6.624 0 6.648 0.192 ;
    END
  END o[57]
  PIN o[58]
    DIRECTION OUTPUT ;
    USE SIGNAL ;
    PORT
      LAYER M3 ;
        RECT  6.696 0 6.714 0.144 ;
    END
  END o[58]
  PIN o[59]
    DIRECTION OUTPUT ;
    USE SIGNAL ;
    PORT
      LAYER M5 ;
        RECT  6.768 0 6.792 0.192 ;
    END
  END o[59]
  PIN o[5]
    DIRECTION OUTPUT ;
    USE SIGNAL ;
    PORT
      LAYER M5 ;
        RECT  2.592 0 2.616 0.192 ;
    END
  END o[5]
  PIN o[60]
    DIRECTION OUTPUT ;
    USE SIGNAL ;
    PORT
      LAYER M3 ;
        RECT  6.876 0 6.894 0.144 ;
    END
  END o[60]
  PIN o[61]
    DIRECTION OUTPUT ;
    USE SIGNAL ;
    PORT
      LAYER M5 ;
        RECT  6.96 0 6.984 0.192 ;
    END
  END o[61]
  PIN o[62]
    DIRECTION OUTPUT ;
    USE SIGNAL ;
    PORT
      LAYER M3 ;
        RECT  7.02 0 7.038 0.144 ;
    END
  END o[62]
  PIN o[63]
    DIRECTION OUTPUT ;
    USE SIGNAL ;
    PORT
      LAYER M5 ;
        RECT  7.104 0 7.128 0.192 ;
    END
  END o[63]
  PIN o[64]
    DIRECTION OUTPUT ;
    USE SIGNAL ;
    PORT
      LAYER M3 ;
        RECT  7.164 0 7.182 0.144 ;
    END
  END o[64]
  PIN o[65]
    DIRECTION OUTPUT ;
    USE SIGNAL ;
    PORT
      LAYER M5 ;
        RECT  7.248 0 7.272 0.192 ;
    END
  END o[65]
  PIN o[66]
    DIRECTION OUTPUT ;
    USE SIGNAL ;
    PORT
      LAYER M3 ;
        RECT  7.344 0 7.362 0.144 ;
    END
  END o[66]
  PIN o[67]
    DIRECTION OUTPUT ;
    USE SIGNAL ;
    PORT
      LAYER M5 ;
        RECT  7.392 0 7.416 0.192 ;
    END
  END o[67]
  PIN o[68]
    DIRECTION OUTPUT ;
    USE SIGNAL ;
    PORT
      LAYER M3 ;
        RECT  7.488 0 7.506 0.144 ;
    END
  END o[68]
  PIN o[69]
    DIRECTION OUTPUT ;
    USE SIGNAL ;
    PORT
      LAYER M5 ;
        RECT  7.584 0 7.608 0.192 ;
    END
  END o[69]
  PIN o[6]
    DIRECTION OUTPUT ;
    USE SIGNAL ;
    PORT
      LAYER M3 ;
        RECT  2.664 0 2.682 0.144 ;
    END
  END o[6]
  PIN o[70]
    DIRECTION OUTPUT ;
    USE SIGNAL ;
    PORT
      LAYER M3 ;
        RECT  7.632 0 7.65 0.144 ;
    END
  END o[70]
  PIN o[71]
    DIRECTION OUTPUT ;
    USE SIGNAL ;
    PORT
      LAYER M5 ;
        RECT  7.728 0 7.752 0.192 ;
    END
  END o[71]
  PIN o[72]
    DIRECTION OUTPUT ;
    USE SIGNAL ;
    PORT
      LAYER M3 ;
        RECT  7.812 0 7.83 0.144 ;
    END
  END o[72]
  PIN o[73]
    DIRECTION OUTPUT ;
    USE SIGNAL ;
    PORT
      LAYER M5 ;
        RECT  7.872 0 7.896 0.192 ;
    END
  END o[73]
  PIN o[74]
    DIRECTION OUTPUT ;
    USE SIGNAL ;
    PORT
      LAYER M3 ;
        RECT  7.956 0 7.974 0.144 ;
    END
  END o[74]
  PIN o[75]
    DIRECTION OUTPUT ;
    USE SIGNAL ;
    PORT
      LAYER M5 ;
        RECT  8.016 0 8.04 0.192 ;
    END
  END o[75]
  PIN o[76]
    DIRECTION OUTPUT ;
    USE SIGNAL ;
    PORT
      LAYER M3 ;
        RECT  8.1 0 8.118 0.144 ;
    END
  END o[76]
  PIN o[77]
    DIRECTION OUTPUT ;
    USE SIGNAL ;
    PORT
      LAYER M5 ;
        RECT  8.208 0 8.232 0.192 ;
    END
  END o[77]
  PIN o[78]
    DIRECTION OUTPUT ;
    USE SIGNAL ;
    PORT
      LAYER M3 ;
        RECT  8.28 0 8.298 0.144 ;
    END
  END o[78]
  PIN o[79]
    DIRECTION OUTPUT ;
    USE SIGNAL ;
    PORT
      LAYER M5 ;
        RECT  8.352 0 8.376 0.192 ;
    END
  END o[79]
  PIN o[7]
    DIRECTION OUTPUT ;
    USE SIGNAL ;
    PORT
      LAYER M5 ;
        RECT  2.736 0 2.76 0.192 ;
    END
  END o[7]
  PIN o[80]
    DIRECTION OUTPUT ;
    USE SIGNAL ;
    PORT
      LAYER M3 ;
        RECT  8.424 0 8.442 0.144 ;
    END
  END o[80]
  PIN o[81]
    DIRECTION OUTPUT ;
    USE SIGNAL ;
    PORT
      LAYER M5 ;
        RECT  8.496 0 8.52 0.192 ;
    END
  END o[81]
  PIN o[82]
    DIRECTION OUTPUT ;
    USE SIGNAL ;
    PORT
      LAYER M3 ;
        RECT  8.568 0 8.586 0.144 ;
    END
  END o[82]
  PIN o[83]
    DIRECTION OUTPUT ;
    USE SIGNAL ;
    PORT
      LAYER M5 ;
        RECT  8.64 0 8.664 0.192 ;
    END
  END o[83]
  PIN o[84]
    DIRECTION OUTPUT ;
    USE SIGNAL ;
    PORT
      LAYER M3 ;
        RECT  8.748 0 8.766 0.144 ;
    END
  END o[84]
  PIN o[85]
    DIRECTION OUTPUT ;
    USE SIGNAL ;
    PORT
      LAYER M5 ;
        RECT  8.832 0 8.856 0.192 ;
    END
  END o[85]
  PIN o[86]
    DIRECTION OUTPUT ;
    USE SIGNAL ;
    PORT
      LAYER M3 ;
        RECT  8.892 0 8.91 0.144 ;
    END
  END o[86]
  PIN o[87]
    DIRECTION OUTPUT ;
    USE SIGNAL ;
    PORT
      LAYER M5 ;
        RECT  8.976 0 9 0.192 ;
    END
  END o[87]
  PIN o[88]
    DIRECTION OUTPUT ;
    USE SIGNAL ;
    PORT
      LAYER M3 ;
        RECT  9.036 0 9.054 0.144 ;
    END
  END o[88]
  PIN o[89]
    DIRECTION OUTPUT ;
    USE SIGNAL ;
    PORT
      LAYER M5 ;
        RECT  9.12 0 9.144 0.192 ;
    END
  END o[89]
  PIN o[8]
    DIRECTION OUTPUT ;
    USE SIGNAL ;
    PORT
      LAYER M3 ;
        RECT  2.808 0 2.826 0.144 ;
    END
  END o[8]
  PIN o[90]
    DIRECTION OUTPUT ;
    USE SIGNAL ;
    PORT
      LAYER M3 ;
        RECT  9.216 0 9.234 0.144 ;
    END
  END o[90]
  PIN o[91]
    DIRECTION OUTPUT ;
    USE SIGNAL ;
    PORT
      LAYER M5 ;
        RECT  9.264 0 9.288 0.192 ;
    END
  END o[91]
  PIN o[92]
    DIRECTION OUTPUT ;
    USE SIGNAL ;
    PORT
      LAYER M3 ;
        RECT  9.36 0 9.378 0.144 ;
    END
  END o[92]
  PIN o[93]
    DIRECTION OUTPUT ;
    USE SIGNAL ;
    PORT
      LAYER M5 ;
        RECT  9.456 0 9.48 0.192 ;
    END
  END o[93]
  PIN o[94]
    DIRECTION OUTPUT ;
    USE SIGNAL ;
    PORT
      LAYER M3 ;
        RECT  9.504 0 9.522 0.144 ;
    END
  END o[94]
  PIN o[95]
    DIRECTION OUTPUT ;
    USE SIGNAL ;
    PORT
      LAYER M5 ;
        RECT  9.6 0 9.624 0.192 ;
    END
  END o[95]
  PIN o[96]
    DIRECTION OUTPUT ;
    USE SIGNAL ;
    PORT
      LAYER M3 ;
        RECT  9.684 0 9.702 0.144 ;
    END
  END o[96]
  PIN o[97]
    DIRECTION OUTPUT ;
    USE SIGNAL ;
    PORT
      LAYER M5 ;
        RECT  9.744 0 9.768 0.192 ;
    END
  END o[97]
  PIN o[98]
    DIRECTION OUTPUT ;
    USE SIGNAL ;
    PORT
      LAYER M3 ;
        RECT  9.828 0 9.846 0.144 ;
    END
  END o[98]
  PIN o[99]
    DIRECTION OUTPUT ;
    USE SIGNAL ;
    PORT
      LAYER M5 ;
        RECT  9.888 0 9.912 0.192 ;
    END
  END o[99]
  PIN o[9]
    DIRECTION OUTPUT ;
    USE SIGNAL ;
    PORT
      LAYER M5 ;
        RECT  2.88 0 2.904 0.192 ;
    END
  END o[9]
  PIN rs
    DIRECTION INPUT ;
    USE SIGNAL ;
    PORT
      LAYER M4 ;
        RECT  25.728 11.904 25.92 11.928 ;
    END
  END rs
  PIN VDD
    DIRECTION INOUT ;
    USE POWER ;
    PORT
      LAYER M5 ;
        RECT  21.492 2.151 21.612 15.129 ;
        RECT  18.792 2.151 18.912 15.129 ;
        RECT  16.092 2.151 16.212 15.129 ;
        RECT  13.392 2.151 13.512 15.129 ;
        RECT  10.692 2.151 10.812 15.129 ;
        RECT  7.992 2.151 8.112 15.129 ;
        RECT  5.292 2.151 5.412 15.129 ;
        RECT  2.592 2.151 2.712 15.129 ;
    END
  END VDD
  PIN VSS
    DIRECTION INOUT ;
    USE GROUND ;
    PORT
      LAYER M5 ;
        RECT  21.3 2.137 21.42 15.143 ;
        RECT  18.6 2.137 18.72 15.143 ;
        RECT  15.9 2.137 16.02 15.143 ;
        RECT  13.2 2.137 13.32 15.143 ;
        RECT  10.5 2.137 10.62 15.143 ;
        RECT  7.8 2.137 7.92 15.143 ;
        RECT  5.1 2.137 5.22 15.143 ;
        RECT  2.4 2.137 2.52 15.143 ;
    END
  END VSS
  OBS
    LAYER RVTN ;
     RECT  2.16 2.16 23.76 2.295 ;
     RECT  2.16 2.565 23.76 2.835 ;
     RECT  2.16 3.105 23.76 3.375 ;
     RECT  2.16 3.645 23.76 3.915 ;
     RECT  2.16 4.185 23.76 4.455 ;
     RECT  2.16 4.725 23.76 4.995 ;
     RECT  2.16 5.265 23.76 5.535 ;
     RECT  2.16 5.805 23.76 6.075 ;
     RECT  2.16 6.345 23.76 6.615 ;
     RECT  2.16 6.885 23.76 7.155 ;
     RECT  2.16 7.425 23.76 7.695 ;
     RECT  2.16 7.965 23.76 8.235 ;
     RECT  2.16 8.505 23.76 8.775 ;
     RECT  2.16 9.045 23.76 9.315 ;
     RECT  2.16 9.585 23.76 9.855 ;
     RECT  2.16 10.125 23.76 10.395 ;
     RECT  2.16 10.665 23.76 10.935 ;
     RECT  2.16 11.205 23.76 11.475 ;
     RECT  2.16 11.745 23.76 12.015 ;
     RECT  2.16 12.285 23.76 12.555 ;
     RECT  2.16 12.825 23.76 13.095 ;
     RECT  2.16 13.365 23.76 13.635 ;
     RECT  2.16 13.905 23.76 14.175 ;
     RECT  2.16 14.445 23.76 14.715 ;
     RECT  2.16 14.985 23.76 15.12 ;
    LAYER RVTP ;
     RECT  2.16 2.295 23.76 2.565 ;
     RECT  2.16 2.835 23.76 3.105 ;
     RECT  2.16 3.375 23.76 3.645 ;
     RECT  2.16 3.915 23.76 4.185 ;
     RECT  2.16 4.455 23.76 4.725 ;
     RECT  2.16 4.995 23.76 5.265 ;
     RECT  2.16 5.535 23.76 5.805 ;
     RECT  2.16 6.075 23.76 6.345 ;
     RECT  2.16 6.615 23.76 6.885 ;
     RECT  2.16 7.155 23.76 7.425 ;
     RECT  2.16 7.695 23.76 7.965 ;
     RECT  2.16 8.235 23.76 8.505 ;
     RECT  2.16 8.775 23.76 9.045 ;
     RECT  2.16 9.315 23.76 9.585 ;
     RECT  2.16 9.855 23.76 10.125 ;
     RECT  2.16 10.395 23.76 10.665 ;
     RECT  2.16 10.935 23.76 11.205 ;
     RECT  2.16 11.475 23.76 11.745 ;
     RECT  2.16 12.015 23.76 12.285 ;
     RECT  2.16 12.555 23.76 12.825 ;
     RECT  2.16 13.095 23.76 13.365 ;
     RECT  2.16 13.635 23.76 13.905 ;
     RECT  2.16 14.175 23.76 14.445 ;
     RECT  2.16 14.715 23.76 14.985 ;
    LAYER M1 ;
     RECT  2.16 2.151 23.76 15.129 ;
    LAYER M2 ;
     RECT  1.003 14.796 1.039 14.814 ;
     RECT  1.003 7.668 1.111 7.686 ;
     RECT  1.039 6.588 1.435 6.606 ;
     RECT  1.039 14.526 1.471 14.814 ;
     RECT  1.075 5.274 1.507 5.292 ;
     RECT  1.435 6.246 1.543 6.606 ;
     RECT  1.507 13.446 1.543 13.464 ;
     RECT  1.543 6.12 1.579 6.606 ;
     RECT  1.507 5.076 1.651 5.292 ;
     RECT  1.579 6.084 1.651 6.606 ;
     RECT  1.471 14.526 1.651 15.21 ;
     RECT  1.543 12.906 1.687 13.464 ;
     RECT  1.651 14.256 1.687 15.21 ;
     RECT  1.651 5.076 1.831 6.606 ;
     RECT  1.111 7.668 1.831 7.722 ;
     RECT  1.687 12.906 1.831 15.21 ;
     RECT  1.687 10.746 1.939 10.764 ;
     RECT  1.831 5.076 2.047 7.722 ;
     RECT  1.831 12.87 2.047 15.21 ;
     RECT  1.939 10.17 2.083 10.764 ;
     RECT  1.903 8.748 2.155 8.766 ;
     RECT  1.975 2.808 2.16 2.826 ;
     RECT  0.967 3.654 2.16 3.672 ;
     RECT  2.047 5.076 2.16 7.758 ;
     RECT  2.155 8.676 2.16 8.766 ;
     RECT  2.083 10.17 2.16 10.998 ;
     RECT  1.435 12.096 2.16 12.114 ;
     RECT  2.047 12.87 2.16 15.246 ;
     RECT  2.299 0.144 2.371 0.162 ;
     RECT  2.335 17.118 2.371 17.136 ;
     RECT  2.371 0.144 2.507 0.234 ;
     RECT  2.371 17.118 2.651 17.208 ;
     RECT  2.507 0.216 2.687 0.234 ;
     RECT  4.207 0.144 4.243 0.162 ;
     RECT  4.243 0.144 4.315 0.198 ;
     RECT  2.16 2.151 4.423 15.246 ;
     RECT  4.315 0.144 4.559 0.279 ;
     RECT  4.423 2.151 4.567 15.399 ;
     RECT  4.559 0.144 5.495 0.234 ;
     RECT  5.467 1.224 5.539 1.242 ;
     RECT  5.539 1.152 5.567 1.242 ;
     RECT  5.567 1.152 5.891 1.206 ;
     RECT  5.891 1.152 5.927 1.17 ;
     RECT  4.567 2.151 6.035 15.444 ;
     RECT  6.035 2.151 6.287 15.354 ;
     RECT  6.287 2.151 6.655 15.246 ;
     RECT  6.691 17.19 6.727 17.208 ;
     RECT  6.727 17.118 6.827 17.208 ;
     RECT  6.655 2.106 7.403 15.246 ;
     RECT  7.403 2.151 7.835 15.246 ;
     RECT  5.495 0.144 8.743 0.162 ;
     RECT  7.231 1.152 8.815 1.17 ;
     RECT  8.743 0.144 8.843 0.234 ;
     RECT  8.815 1.152 9.023 1.242 ;
     RECT  7.835 2.151 9.139 15.21 ;
     RECT  9.139 2.106 9.887 15.21 ;
     RECT  8.843 0.144 10.255 0.162 ;
     RECT  10.255 0.144 10.327 0.234 ;
     RECT  10.291 17.19 10.327 17.208 ;
     RECT  9.887 2.151 10.363 15.21 ;
     RECT  10.327 0.144 10.391 0.279 ;
     RECT  10.327 17.118 10.427 17.208 ;
     RECT  10.363 2.151 10.499 15.354 ;
     RECT  10.391 0.261 10.643 0.279 ;
     RECT  10.499 2.151 10.823 15.246 ;
     RECT  10.823 2.151 11.371 15.21 ;
     RECT  11.803 0.576 11.839 0.594 ;
     RECT  11.371 2.106 11.911 15.21 ;
     RECT  11.911 2.034 12.587 15.21 ;
     RECT  12.587 2.106 13.199 15.21 ;
     RECT  13.199 2.151 13.315 15.21 ;
     RECT  11.839 0.144 13.451 0.594 ;
     RECT  13.315 2.151 13.595 15.399 ;
     RECT  13.595 2.151 13.631 15.318 ;
     RECT  13.631 2.151 14.171 15.21 ;
     RECT  13.451 0.144 14.675 0.162 ;
     RECT  14.171 2.151 14.791 15.174 ;
     RECT  14.791 2.106 15.439 15.174 ;
     RECT  15.439 2.034 15.619 15.174 ;
     RECT  15.619 2.034 15.691 15.21 ;
     RECT  15.691 1.962 15.971 15.21 ;
     RECT  15.727 0.144 16.735 0.162 ;
     RECT  16.735 0.144 16.871 0.198 ;
     RECT  16.871 0.144 16.979 0.162 ;
     RECT  15.971 1.962 17.167 15.129 ;
     RECT  17.167 1.152 17.311 1.17 ;
     RECT  17.167 1.962 17.311 15.174 ;
     RECT  17.311 1.152 17.663 15.174 ;
     RECT  17.779 0.144 17.923 0.162 ;
     RECT  17.663 1.962 18.427 15.174 ;
     RECT  16.411 16.236 18.463 16.254 ;
     RECT  18.463 16.236 18.563 16.704 ;
     RECT  18.931 1.152 19.147 1.17 ;
     RECT  18.427 1.962 19.147 15.282 ;
     RECT  19.147 1.152 19.283 15.282 ;
     RECT  19.075 17.082 19.363 17.1 ;
     RECT  19.363 17.082 19.391 17.172 ;
     RECT  17.923 0.144 19.687 0.234 ;
     RECT  19.687 0.144 20.011 0.864 ;
     RECT  20.011 0.144 20.119 1.17 ;
     RECT  19.283 1.962 20.119 15.282 ;
     RECT  20.119 0.144 20.335 15.282 ;
     RECT  20.335 0.144 20.399 15.318 ;
     RECT  20.399 0.846 20.875 15.318 ;
     RECT  20.875 0.846 21.487 15.354 ;
     RECT  18.563 16.236 21.487 16.254 ;
     RECT  21.487 0.846 21.523 16.254 ;
     RECT  21.523 0.144 21.659 16.254 ;
     RECT  21.659 15.921 22.451 16.254 ;
     RECT  21.659 0.144 22.739 15.174 ;
     RECT  19.391 17.154 23.207 17.172 ;
     RECT  22.739 0.144 23.243 0.864 ;
     RECT  23.243 0.216 23.279 0.864 ;
     RECT  22.451 15.921 23.279 15.939 ;
     RECT  22.739 1.881 23.423 15.174 ;
     RECT  23.279 0.846 23.747 0.864 ;
     RECT  23.423 2.151 23.76 15.174 ;
     RECT  23.76 10.566 23.783 15.174 ;
     RECT  23.783 10.566 23.891 11.574 ;
     RECT  23.76 7.74 23.963 9.036 ;
     RECT  23.963 7.74 24.071 8.604 ;
     RECT  23.76 4.464 24.143 5.328 ;
     RECT  23.783 12.33 24.143 15.174 ;
     RECT  24.143 12.636 24.179 15.174 ;
     RECT  23.891 11.25 24.251 11.574 ;
     RECT  24.251 11.286 24.287 11.574 ;
     RECT  24.143 5.31 24.323 5.328 ;
     RECT  24.071 7.74 24.359 8.568 ;
     RECT  24.179 12.636 24.359 12.924 ;
     RECT  24.359 8.01 24.539 8.568 ;
     RECT  24.287 11.286 24.539 11.304 ;
     RECT  24.143 4.464 24.647 4.554 ;
     RECT  23.76 2.304 25.115 3.708 ;
     RECT  23.76 6.156 25.151 6.174 ;
     RECT  24.179 13.878 25.151 15.174 ;
     RECT  24.539 8.55 25.187 8.568 ;
     RECT  25.115 2.304 25.223 3.402 ;
     RECT  25.151 13.986 25.223 15.174 ;
     RECT  25.223 2.376 25.259 3.402 ;
     RECT  24.647 4.536 25.331 4.554 ;
     RECT  24.359 12.636 25.331 12.654 ;
     RECT  25.259 2.376 25.367 2.862 ;
     RECT  25.223 14.454 25.367 15.174 ;
     RECT  25.367 2.538 25.403 2.862 ;
     RECT  25.367 14.526 25.403 15.174 ;
     RECT  25.403 2.844 25.439 2.862 ;
     RECT  25.403 15.156 25.439 15.174 ;
    LAYER M3 ;
     RECT  2.196 0.108 23.742 0.869 ;
     RECT  2.196 0.869 23.562 2.299 ;
     RECT  25.2 2.299 25.218 2.371 ;
     RECT  2.196 2.299 24.354 2.444 ;
     RECT  25.2 2.371 25.362 2.533 ;
     RECT  2.196 2.444 24.246 2.803 ;
     RECT  25.2 2.533 25.398 2.839 ;
     RECT  1.98 2.803 24.246 3.451 ;
     RECT  25.2 2.839 25.434 3.685 ;
     RECT  1.98 3.451 24.282 4.459 ;
     RECT  25.092 3.685 25.434 4.459 ;
     RECT  0.972 3.649 0.99 5.071 ;
     RECT  1.98 4.459 25.434 5.071 ;
     RECT  0.972 5.071 25.434 7.579 ;
     RECT  0.972 7.579 25.758 11.453 ;
     RECT  0.972 11.453 25.686 11.933 ;
     RECT  0.972 11.933 25.434 12.077 ;
     RECT  1.008 12.077 25.434 13.421 ;
     RECT  1.008 13.421 24.174 13.469 ;
     RECT  25.128 13.421 25.434 13.901 ;
     RECT  25.164 13.901 25.434 14.513 ;
     RECT  25.38 14.513 25.434 14.549 ;
     RECT  1.008 13.469 24.102 14.813 ;
     RECT  1.008 14.813 23.814 14.819 ;
     RECT  25.416 14.549 25.434 15.179 ;
     RECT  1.476 14.819 23.814 15.215 ;
     RECT  2.052 15.215 23.814 15.251 ;
     RECT  2.16 15.251 23.814 15.677 ;
     RECT  2.196 15.677 23.814 17.117 ;
     RECT  2.196 17.117 23.634 17.148 ;
     RECT  19.368 17.148 19.386 17.177 ;
     RECT  23.184 17.148 23.202 17.177 ;
     RECT  2.376 17.148 2.646 17.213 ;
     RECT  6.696 17.148 6.822 17.213 ;
     RECT  10.296 17.148 10.422 17.213 ;
    LAYER M4 ;
     RECT  0.229 3.072 0.277 3.096 ;
     RECT  0.229 14.4 0.277 14.424 ;
     RECT  0.277 14.208 0.325 14.424 ;
     RECT  0.325 14.208 0.421 15.288 ;
     RECT  0.325 10.176 0.469 10.2 ;
     RECT  0.373 7.92 0.517 7.944 ;
     RECT  0.277 2.784 0.757 3.096 ;
     RECT  0.421 14.208 0.757 15.336 ;
     RECT  0.421 5.52 0.805 5.544 ;
     RECT  0.517 7.68 0.853 7.944 ;
     RECT  0.469 9.888 0.901 10.2 ;
     RECT  0.805 5.472 0.949 5.544 ;
     RECT  0.757 13.392 0.997 15.336 ;
     RECT  0.961 12.048 1.045 12.072 ;
     RECT  0.997 13.152 1.045 15.336 ;
     RECT  0.901 9.36 1.093 10.2 ;
     RECT  0.757 2.496 1.333 3.096 ;
     RECT  0.997 4.416 1.381 4.44 ;
     RECT  1.045 12.048 1.436 15.336 ;
     RECT  0.853 7.632 1.477 7.944 ;
     RECT  1.093 9.36 1.477 10.824 ;
     RECT  0.949 5.472 1.525 5.784 ;
     RECT  1.525 5.472 1.573 5.88 ;
     RECT  1.477 7.632 1.789 10.824 ;
     RECT  1.333 2.496 1.861 3.336 ;
     RECT  1.861 2.496 1.909 3.384 ;
     RECT  1.381 4.416 1.909 4.488 ;
     RECT  1.573 5.472 2.005 6.024 ;
     RECT  1.789 7.632 2.053 10.92 ;
     RECT  1.436 11.952 2.053 15.336 ;
     RECT  1.909 2.496 2.101 4.488 ;
     RECT  2.005 5.472 2.101 6.072 ;
     RECT  2.053 7.632 2.101 15.336 ;
     RECT  2.101 7.632 2.149 15.384 ;
     RECT  2.149 7.632 2.197 15.672 ;
     RECT  2.101 2.496 2.245 6.072 ;
     RECT  2.245 1.728 2.408 6.072 ;
     RECT  2.197 7.632 2.408 16.248 ;
     RECT  2.293 0.336 2.581 0.36 ;
     RECT  2.408 1.728 2.704 16.248 ;
     RECT  2.581 0.288 2.869 0.36 ;
     RECT  2.704 1.728 2.869 6.072 ;
     RECT  2.869 0.288 3.413 6.072 ;
     RECT  3.413 1.68 3.781 6.072 ;
     RECT  2.704 7.392 3.781 16.248 ;
     RECT  3.413 0.288 3.805 0.6 ;
     RECT  3.805 0.192 3.809 0.6 ;
     RECT  3.781 1.68 3.881 16.248 ;
     RECT  3.809 0.192 3.889 0.216 ;
     RECT  3.881 1.68 4.499 6.408 ;
     RECT  4.499 1.728 5.108 6.408 ;
     RECT  3.881 7.392 5.108 16.248 ;
     RECT  4.981 0.192 5.123 0.216 ;
     RECT  5.701 0.576 6.509 0.6 ;
     RECT  5.108 1.728 7.237 16.248 ;
     RECT  7.237 1.728 7.475 16.584 ;
     RECT  7.475 1.728 7.657 16.248 ;
     RECT  7.657 1.68 7.763 16.248 ;
     RECT  7.669 0.144 8.005 0.168 ;
     RECT  7.763 1.728 8.104 16.248 ;
     RECT  8.005 0.144 8.243 0.312 ;
     RECT  8.104 5.472 8.579 16.248 ;
     RECT  8.104 1.728 9.349 4.488 ;
     RECT  8.579 5.472 9.349 6.312 ;
     RECT  9.349 1.728 9.443 6.312 ;
     RECT  8.579 7.632 9.685 16.248 ;
     RECT  9.685 7.392 9.771 16.248 ;
     RECT  8.243 0.144 9.877 0.168 ;
     RECT  9.877 0.144 10.217 0.6 ;
     RECT  9.443 1.728 10.357 4.488 ;
     RECT  10.357 1.68 10.508 4.488 ;
     RECT  9.443 5.712 10.508 6.312 ;
     RECT  9.771 7.344 10.508 16.248 ;
     RECT  10.508 1.68 10.547 16.248 ;
     RECT  10.547 1.728 10.595 16.248 ;
     RECT  10.595 1.728 10.804 15.24 ;
     RECT  10.804 5.76 10.865 15.24 ;
     RECT  10.804 1.728 10.973 3.384 ;
     RECT  10.804 4.416 11.225 4.488 ;
     RECT  10.595 16.224 11.557 16.248 ;
     RECT  10.865 5.856 11.689 15.24 ;
     RECT  11.557 16.224 11.689 16.584 ;
     RECT  10.217 0.144 11.749 0.312 ;
     RECT  11.689 5.856 11.908 16.584 ;
     RECT  11.908 5.856 11.945 16.632 ;
     RECT  11.945 7.44 12.083 16.632 ;
     RECT  11.749 0.144 12.085 0.552 ;
     RECT  10.973 1.728 12.085 3.048 ;
     RECT  11.945 5.856 12.089 6.024 ;
     RECT  12.089 5.856 12.161 5.88 ;
     RECT  12.085 0.144 12.413 3.048 ;
     RECT  12.413 0.144 12.701 0.216 ;
     RECT  12.701 0.144 12.989 0.168 ;
     RECT  11.225 4.464 13.093 4.488 ;
     RECT  12.373 5.52 13.093 5.736 ;
     RECT  12.413 1.728 13.208 3.048 ;
     RECT  13.093 4.464 13.208 5.736 ;
     RECT  12.083 7.44 13.208 16.248 ;
     RECT  13.208 1.728 13.504 16.248 ;
     RECT  13.504 7.632 13.667 16.248 ;
     RECT  13.916 0.528 14.147 0.552 ;
     RECT  13.504 1.728 14.605 3.096 ;
     RECT  13.504 4.176 14.605 5.304 ;
     RECT  13.667 16.224 14.713 16.248 ;
     RECT  13.504 6.576 14.725 6.6 ;
     RECT  13.667 7.632 14.725 14.808 ;
     RECT  14.725 6.576 15.013 14.808 ;
     RECT  14.605 1.728 15.073 5.304 ;
     RECT  15.013 6.576 15.073 14.904 ;
     RECT  15.073 1.728 15.445 14.904 ;
     RECT  14.713 16.224 15.445 16.584 ;
     RECT  14.245 0.192 15.913 0.216 ;
     RECT  15.445 1.728 16.021 16.584 ;
     RECT  16.297 0.528 16.309 0.552 ;
     RECT  16.021 1.728 16.445 16.632 ;
     RECT  16.445 1.728 16.451 15.24 ;
     RECT  16.451 6.576 16.489 15.24 ;
     RECT  16.445 16.224 16.501 16.632 ;
     RECT  16.309 0.528 17.077 0.6 ;
     RECT  16.451 1.728 17.077 5.4 ;
     RECT  16.501 16.224 17.089 17.016 ;
     RECT  17.077 0.528 17.413 5.4 ;
     RECT  17.413 0.528 17.701 5.496 ;
     RECT  16.489 6.576 17.701 15 ;
     RECT  17.089 16.224 17.701 17.112 ;
     RECT  17.701 16.176 17.785 17.112 ;
     RECT  17.701 0.528 18.305 15 ;
     RECT  18.305 0.192 18.373 15 ;
     RECT  18.373 0.192 19.043 15.24 ;
     RECT  19.043 0.192 20.333 15.048 ;
     RECT  20.333 0.576 21.109 15.048 ;
     RECT  21.109 0.576 21.161 15.24 ;
     RECT  21.161 1.104 21.349 15.24 ;
     RECT  17.785 16.224 21.349 17.112 ;
     RECT  21.349 1.104 21.701 17.112 ;
     RECT  21.701 16.224 22.493 17.112 ;
     RECT  21.701 1.104 23.507 15.048 ;
     RECT  23.507 1.68 23.651 15.048 ;
     RECT  23.651 2.064 23.747 15.048 ;
     RECT  23.747 2.064 23.789 9.096 ;
     RECT  23.789 6.576 23.795 9.096 ;
     RECT  22.493 16.56 23.795 17.112 ;
     RECT  23.747 10.08 23.825 15.048 ;
     RECT  23.795 16.656 23.825 17.112 ;
     RECT  23.795 6.576 23.861 8.28 ;
     RECT  23.789 2.064 24.131 5.448 ;
     RECT  24.131 2.544 24.179 5.448 ;
     RECT  24.179 2.544 24.227 3.384 ;
     RECT  24.227 2.544 24.323 3.336 ;
     RECT  23.825 10.128 24.563 15.048 ;
     RECT  23.825 16.656 24.563 16.68 ;
     RECT  23.861 7.584 24.611 8.28 ;
     RECT  23.861 6.576 24.617 6.6 ;
     RECT  24.563 10.896 24.659 15.048 ;
     RECT  24.179 4.416 24.707 5.448 ;
     RECT  24.659 10.896 24.707 14.472 ;
     RECT  24.323 2.784 24.755 3.336 ;
     RECT  24.707 11.424 24.755 14.472 ;
     RECT  24.755 2.784 24.803 2.808 ;
     RECT  24.755 13.44 24.803 14.472 ;
     RECT  24.803 13.44 25.265 13.992 ;
     RECT  24.707 4.416 25.301 4.44 ;
     RECT  25.265 13.968 25.301 13.992 ;
     RECT  24.707 5.424 25.74 5.448 ;
     RECT  24.755 11.424 25.74 11.928 ;
     RECT  24.611 7.584 25.769 7.608 ;
     RECT  25.74 11.424 25.769 11.448 ;
    LAYER M5 ;
     RECT  7.68 0.133 7.704 0.144 ;
     RECT  2.256 0.144 23.64 1.763 ;
     RECT  2.304 1.763 23.64 1.859 ;
     RECT  20.976 1.859 23.64 2.053 ;
     RECT  2.304 1.859 19.896 2.339 ;
     RECT  20.976 2.053 24.12 2.339 ;
     RECT  21.3 2.339 24.12 2.533 ;
     RECT  2.304 2.339 14.616 2.579 ;
     RECT  15.9 2.339 19.896 2.723 ;
     RECT  0.768 2.485 0.792 2.773 ;
     RECT  21.3 2.533 24.312 2.773 ;
     RECT  2.304 2.579 11.496 2.819 ;
     RECT  2.304 2.819 11.352 2.821 ;
     RECT  2.064 2.821 11.352 2.867 ;
     RECT  12.864 2.579 14.616 2.867 ;
     RECT  2.064 2.867 10.968 2.963 ;
     RECT  0.288 2.773 0.792 3.061 ;
     RECT  12.864 2.867 13.656 3.107 ;
     RECT  2.064 2.963 10.812 3.109 ;
     RECT  0.24 3.061 0.792 3.301 ;
     RECT  1.968 3.109 10.812 3.301 ;
     RECT  15.9 2.723 18.912 3.925 ;
     RECT  21.3 2.773 24.792 4.117 ;
     RECT  15.792 3.925 18.912 4.595 ;
     RECT  20.976 4.117 24.792 4.933 ;
     RECT  20.832 4.933 24.792 5.077 ;
     RECT  17.472 4.595 18.912 5.317 ;
     RECT  12.864 3.107 13.512 5.509 ;
     RECT  15.792 4.595 16.212 5.747 ;
     RECT  17.472 5.317 19.704 5.747 ;
     RECT  0.24 3.301 10.812 5.843 ;
     RECT  18.6 5.747 19.704 6.037 ;
     RECT  20.784 5.077 24.792 6.037 ;
     RECT  15.9 5.747 16.212 6.085 ;
     RECT  6.432 5.843 10.812 6.277 ;
     RECT  6.432 6.277 11.208 6.661 ;
     RECT  12.384 5.509 13.512 6.661 ;
     RECT  14.64 3.925 14.664 6.661 ;
     RECT  15.9 6.085 16.44 6.805 ;
     RECT  17.472 5.747 17.496 6.805 ;
     RECT  18.6 6.037 24.792 6.805 ;
     RECT  14.64 6.661 14.76 7.429 ;
     RECT  15.9 6.805 24.792 7.429 ;
     RECT  6.432 6.661 13.512 7.909 ;
     RECT  14.64 7.429 24.792 7.909 ;
     RECT  0.24 5.843 5.412 7.957 ;
     RECT  6.432 7.909 24.792 7.957 ;
     RECT  0.24 7.957 24.792 14.435 ;
     RECT  0.336 14.435 24.792 14.483 ;
     RECT  0.336 14.483 24.648 15.011 ;
     RECT  2.112 15.011 24.648 15.059 ;
     RECT  0.336 15.011 0.84 15.251 ;
     RECT  0.336 15.251 0.456 15.299 ;
     RECT  0.432 15.299 0.456 15.347 ;
     RECT  2.112 15.059 24.552 15.395 ;
     RECT  2.208 15.395 24.552 16.259 ;
     RECT  2.256 16.259 24.552 16.691 ;
     RECT  2.256 16.691 23.736 17.104 ;
  END
END dsfd_dvrly_276_NS
END LIBRARY
